VERSION 5.7 ;
  NOWIREEXTENSIONATPIN ON ;
  DIVIDERCHAR "/" ;
  BUSBITCHARS "[]" ;
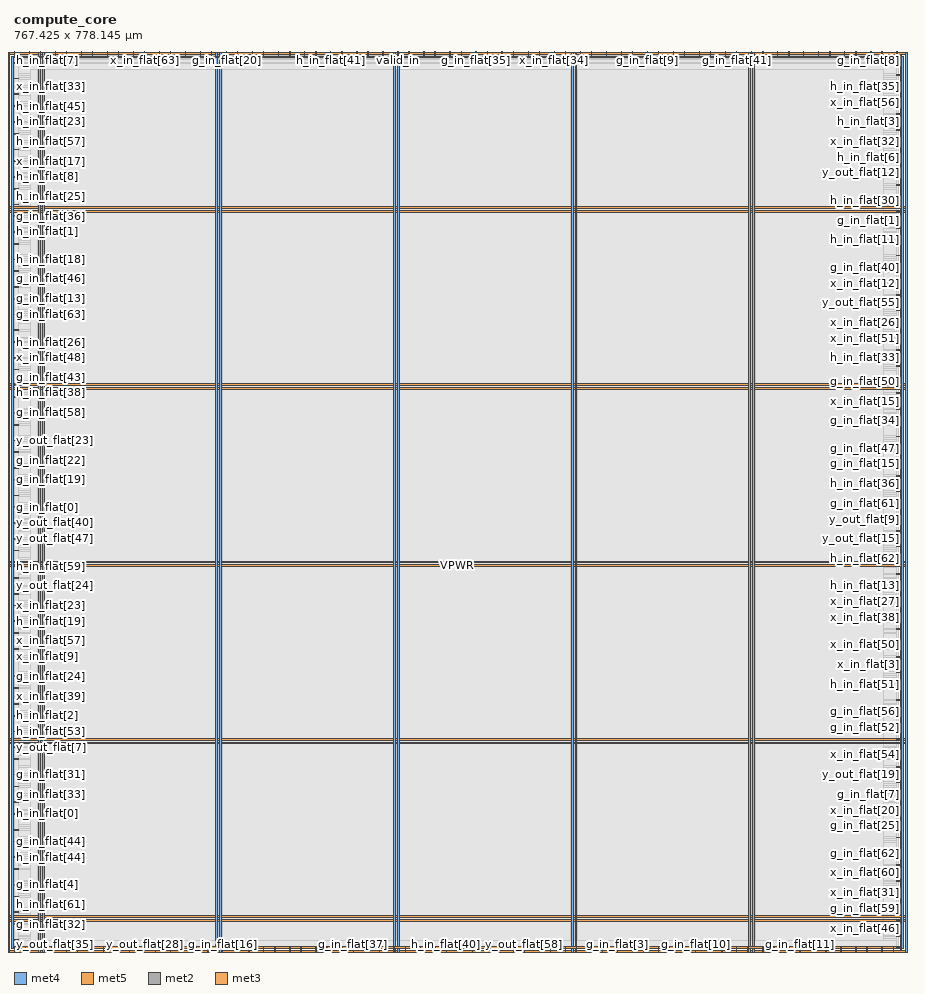
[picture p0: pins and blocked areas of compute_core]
MACRO compute_core
  CLASS BLOCK ;
  FOREIGN compute_core ;
  ORIGIN 0.000 0.000 ;
  SIZE 767.425 BY 778.145 ;
  PIN VGND
    DIRECTION INOUT ;
    USE GROUND ;
    PORT
      LAYER met4 ;
        RECT -5.380 -0.020 -3.780 777.940 ;
    END
    PORT
      LAYER met5 ;
        RECT -5.380 -0.020 772.660 1.580 ;
    END
    PORT
      LAYER met5 ;
        RECT -5.380 776.340 772.660 777.940 ;
    END
    PORT
      LAYER met4 ;
        RECT 771.060 -0.020 772.660 777.940 ;
    END
    PORT
      LAYER met4 ;
        RECT 24.340 -0.020 25.940 777.940 ;
    END
    PORT
      LAYER met4 ;
        RECT 177.940 -0.020 179.540 777.940 ;
    END
    PORT
      LAYER met4 ;
        RECT 331.540 -0.020 333.140 777.940 ;
    END
    PORT
      LAYER met4 ;
        RECT 485.140 -0.020 486.740 777.940 ;
    END
    PORT
      LAYER met4 ;
        RECT 638.740 -0.020 640.340 777.940 ;
    END
    PORT
      LAYER met5 ;
        RECT -5.380 30.030 772.660 31.630 ;
    END
    PORT
      LAYER met5 ;
        RECT -5.380 183.210 772.660 184.810 ;
    END
    PORT
      LAYER met5 ;
        RECT -5.380 336.390 772.660 337.990 ;
    END
    PORT
      LAYER met5 ;
        RECT -5.380 489.570 772.660 491.170 ;
    END
    PORT
      LAYER met5 ;
        RECT -5.380 642.750 772.660 644.350 ;
    END
  END VGND
  PIN VPWR
    DIRECTION INOUT ;
    USE POWER ;
    PORT
      LAYER met4 ;
        RECT -2.080 3.280 -0.480 774.640 ;
    END
    PORT
      LAYER met5 ;
        RECT -2.080 3.280 769.360 4.880 ;
    END
    PORT
      LAYER met5 ;
        RECT -2.080 773.040 769.360 774.640 ;
    END
    PORT
      LAYER met4 ;
        RECT 767.760 3.280 769.360 774.640 ;
    END
    PORT
      LAYER met4 ;
        RECT 21.040 -0.020 22.640 777.940 ;
    END
    PORT
      LAYER met4 ;
        RECT 174.640 -0.020 176.240 777.940 ;
    END
    PORT
      LAYER met4 ;
        RECT 328.240 -0.020 329.840 777.940 ;
    END
    PORT
      LAYER met4 ;
        RECT 481.840 -0.020 483.440 777.940 ;
    END
    PORT
      LAYER met4 ;
        RECT 635.440 -0.020 637.040 777.940 ;
    END
    PORT
      LAYER met5 ;
        RECT -5.380 26.730 772.660 28.330 ;
    END
    PORT
      LAYER met5 ;
        RECT -5.380 179.910 772.660 181.510 ;
    END
    PORT
      LAYER met5 ;
        RECT -5.380 333.090 772.660 334.690 ;
    END
    PORT
      LAYER met5 ;
        RECT -5.380 486.270 772.660 487.870 ;
    END
    PORT
      LAYER met5 ;
        RECT -5.380 639.450 772.660 641.050 ;
    END
  END VPWR
  PIN clk
    DIRECTION INPUT ;
    USE SIGNAL ;
    ANTENNAGATEAREA 1.286700 ;
    ANTENNADIFFAREA 0.434700 ;
    PORT
      LAYER met2 ;
        RECT 80.590 774.145 80.870 778.145 ;
    END
  END clk
  PIN compute_en
    DIRECTION INPUT ;
    USE SIGNAL ;
    ANTENNAGATEAREA 0.495000 ;
    PORT
      LAYER met3 ;
        RECT 0.000 71.440 4.000 72.040 ;
    END
  END compute_en
  PIN g_in_flat[0]
    DIRECTION INPUT ;
    USE SIGNAL ;
    ANTENNAGATEAREA 0.426000 ;
    PORT
      LAYER met3 ;
        RECT 0.000 384.240 4.000 384.840 ;
    END
  END g_in_flat[0]
  PIN g_in_flat[10]
    DIRECTION INPUT ;
    USE SIGNAL ;
    ANTENNAGATEAREA 0.213000 ;
    PORT
      LAYER met2 ;
        RECT 589.350 0.000 589.630 4.000 ;
    END
  END g_in_flat[10]
  PIN g_in_flat[11]
    DIRECTION INPUT ;
    USE SIGNAL ;
    ANTENNAGATEAREA 0.213000 ;
    PORT
      LAYER met2 ;
        RECT 679.510 0.000 679.790 4.000 ;
    END
  END g_in_flat[11]
  PIN g_in_flat[12]
    DIRECTION INPUT ;
    USE SIGNAL ;
    ANTENNAGATEAREA 0.426000 ;
    PORT
      LAYER met2 ;
        RECT 251.250 774.145 251.530 778.145 ;
    END
  END g_in_flat[12]
  PIN g_in_flat[13]
    DIRECTION INPUT ;
    USE SIGNAL ;
    ANTENNAGATEAREA 0.495000 ;
    PORT
      LAYER met3 ;
        RECT 0.000 564.440 4.000 565.040 ;
    END
  END g_in_flat[13]
  PIN g_in_flat[14]
    DIRECTION INPUT ;
    USE SIGNAL ;
    ANTENNAGATEAREA 0.213000 ;
    PORT
      LAYER met3 ;
        RECT 763.425 3.440 767.425 4.040 ;
    END
  END g_in_flat[14]
  PIN g_in_flat[15]
    DIRECTION INPUT ;
    USE SIGNAL ;
    ANTENNAGATEAREA 0.196500 ;
    PORT
      LAYER met3 ;
        RECT 763.425 421.640 767.425 422.240 ;
    END
  END g_in_flat[15]
  PIN g_in_flat[16]
    DIRECTION INPUT ;
    USE SIGNAL ;
    ANTENNAGATEAREA 0.213000 ;
    PORT
      LAYER met2 ;
        RECT 180.410 0.000 180.690 4.000 ;
    END
  END g_in_flat[16]
  PIN g_in_flat[17]
    DIRECTION INPUT ;
    USE SIGNAL ;
    ANTENNAGATEAREA 0.213000 ;
    PORT
      LAYER met3 ;
        RECT 0.000 10.240 4.000 10.840 ;
    END
  END g_in_flat[17]
  PIN g_in_flat[18]
    DIRECTION INPUT ;
    USE SIGNAL ;
    ANTENNAGATEAREA 0.196500 ;
    PORT
      LAYER met2 ;
        RECT 193.290 0.000 193.570 4.000 ;
    END
  END g_in_flat[18]
  PIN g_in_flat[19]
    DIRECTION INPUT ;
    USE SIGNAL ;
    ANTENNAGATEAREA 0.213000 ;
    PORT
      LAYER met3 ;
        RECT 0.000 408.040 4.000 408.640 ;
    END
  END g_in_flat[19]
  PIN g_in_flat[1]
    DIRECTION INPUT ;
    USE SIGNAL ;
    ANTENNAGATEAREA 0.213000 ;
    PORT
      LAYER met3 ;
        RECT 763.425 625.640 767.425 626.240 ;
    END
  END g_in_flat[1]
  PIN g_in_flat[20]
    DIRECTION INPUT ;
    USE SIGNAL ;
    ANTENNAGATEAREA 0.247500 ;
    PORT
      LAYER met2 ;
        RECT 183.630 774.145 183.910 778.145 ;
    END
  END g_in_flat[20]
  PIN g_in_flat[21]
    DIRECTION INPUT ;
    USE SIGNAL ;
    ANTENNAGATEAREA 0.247500 ;
    PORT
      LAYER met2 ;
        RECT 193.290 774.145 193.570 778.145 ;
    END
  END g_in_flat[21]
  PIN g_in_flat[22]
    DIRECTION INPUT ;
    USE SIGNAL ;
    ANTENNAGATEAREA 0.213000 ;
    PORT
      LAYER met3 ;
        RECT 0.000 418.240 4.000 418.840 ;
    END
  END g_in_flat[22]
  PIN g_in_flat[23]
    DIRECTION INPUT ;
    USE SIGNAL ;
    ANTENNAGATEAREA 0.213000 ;
    PORT
      LAYER met2 ;
        RECT 45.170 0.000 45.450 4.000 ;
    END
  END g_in_flat[23]
  PIN g_in_flat[24]
    DIRECTION INPUT ;
    USE SIGNAL ;
    ANTENNAGATEAREA 0.213000 ;
    PORT
      LAYER met3 ;
        RECT 0.000 238.040 4.000 238.640 ;
    END
  END g_in_flat[24]
  PIN g_in_flat[25]
    DIRECTION INPUT ;
    USE SIGNAL ;
    ANTENNAGATEAREA 0.426000 ;
    PORT
      LAYER met3 ;
        RECT 763.425 108.840 767.425 109.440 ;
    END
  END g_in_flat[25]
  PIN g_in_flat[26]
    DIRECTION INPUT ;
    USE SIGNAL ;
    ANTENNAGATEAREA 0.213000 ;
    PORT
      LAYER met2 ;
        RECT 409.030 774.145 409.310 778.145 ;
    END
  END g_in_flat[26]
  PIN g_in_flat[27]
    DIRECTION INPUT ;
    USE SIGNAL ;
    ANTENNAGATEAREA 0.742500 ;
    PORT
      LAYER met2 ;
        RECT 624.770 0.000 625.050 4.000 ;
    END
  END g_in_flat[27]
  PIN g_in_flat[28]
    DIRECTION INPUT ;
    USE SIGNAL ;
    ANTENNAGATEAREA 0.213000 ;
    PORT
      LAYER met2 ;
        RECT 67.710 774.145 67.990 778.145 ;
    END
  END g_in_flat[28]
  PIN g_in_flat[29]
    DIRECTION INPUT ;
    USE SIGNAL ;
    ANTENNAGATEAREA 0.159000 ;
    PORT
      LAYER met2 ;
        RECT 376.830 774.145 377.110 778.145 ;
    END
  END g_in_flat[29]
  PIN g_in_flat[2]
    DIRECTION INPUT ;
    USE SIGNAL ;
    ANTENNAGATEAREA 0.426000 ;
    PORT
      LAYER met2 ;
        RECT 225.490 0.000 225.770 4.000 ;
    END
  END g_in_flat[2]
  PIN g_in_flat[30]
    DIRECTION INPUT ;
    USE SIGNAL ;
    ANTENNAGATEAREA 0.159000 ;
    PORT
      LAYER met2 ;
        RECT 58.050 774.145 58.330 778.145 ;
    END
  END g_in_flat[30]
  PIN g_in_flat[31]
    DIRECTION INPUT ;
    USE SIGNAL ;
    ANTENNAGATEAREA 0.159000 ;
    PORT
      LAYER met3 ;
        RECT 0.000 153.040 4.000 153.640 ;
    END
  END g_in_flat[31]
  PIN g_in_flat[32]
    DIRECTION INPUT ;
    USE SIGNAL ;
    ANTENNAGATEAREA 0.213000 ;
    PORT
      LAYER met3 ;
        RECT 0.000 23.840 4.000 24.440 ;
    END
  END g_in_flat[32]
  PIN g_in_flat[33]
    DIRECTION INPUT ;
    USE SIGNAL ;
    ANTENNAGATEAREA 0.247500 ;
    PORT
      LAYER met3 ;
        RECT 0.000 142.840 4.000 143.440 ;
    END
  END g_in_flat[33]
  PIN g_in_flat[34]
    DIRECTION INPUT ;
    USE SIGNAL ;
    ANTENNAGATEAREA 0.426000 ;
    PORT
      LAYER met3 ;
        RECT 763.425 459.040 767.425 459.640 ;
    END
  END g_in_flat[34]
  PIN g_in_flat[35]
    DIRECTION INPUT ;
    USE SIGNAL ;
    ANTENNAGATEAREA 0.247500 ;
    PORT
      LAYER met2 ;
        RECT 399.370 774.145 399.650 778.145 ;
    END
  END g_in_flat[35]
  PIN g_in_flat[36]
    DIRECTION INPUT ;
    USE SIGNAL ;
    ANTENNAGATEAREA 0.159000 ;
    PORT
      LAYER met3 ;
        RECT 0.000 635.840 4.000 636.440 ;
    END
  END g_in_flat[36]
  PIN g_in_flat[37]
    DIRECTION INPUT ;
    USE SIGNAL ;
    ANTENNAGATEAREA 0.213000 ;
    PORT
      LAYER met2 ;
        RECT 293.110 0.000 293.390 4.000 ;
    END
  END g_in_flat[37]
  PIN g_in_flat[38]
    DIRECTION INPUT ;
    USE SIGNAL ;
    ANTENNAGATEAREA 0.213000 ;
    PORT
      LAYER met2 ;
        RECT 167.530 0.000 167.810 4.000 ;
    END
  END g_in_flat[38]
  PIN g_in_flat[39]
    DIRECTION INPUT ;
    USE SIGNAL ;
    ANTENNAGATEAREA 0.213000 ;
    PORT
      LAYER met2 ;
        RECT 125.670 774.145 125.950 778.145 ;
    END
  END g_in_flat[39]
  PIN g_in_flat[3]
    DIRECTION INPUT ;
    USE SIGNAL ;
    ANTENNAGATEAREA 0.247500 ;
    PORT
      LAYER met2 ;
        RECT 521.730 0.000 522.010 4.000 ;
    END
  END g_in_flat[3]
  PIN g_in_flat[40]
    DIRECTION INPUT ;
    USE SIGNAL ;
    ANTENNAGATEAREA 0.495000 ;
    PORT
      LAYER met3 ;
        RECT 763.425 591.640 767.425 592.240 ;
    END
  END g_in_flat[40]
  PIN g_in_flat[41]
    DIRECTION INPUT ;
    USE SIGNAL ;
    ANTENNAGATEAREA 0.742500 ;
    PORT
      LAYER met2 ;
        RECT 624.770 774.145 625.050 778.145 ;
    END
  END g_in_flat[41]
  PIN g_in_flat[42]
    DIRECTION INPUT ;
    USE SIGNAL ;
    ANTENNAGATEAREA 0.247500 ;
    PORT
      LAYER met2 ;
        RECT 238.370 774.145 238.650 778.145 ;
    END
  END g_in_flat[42]
  PIN g_in_flat[43]
    DIRECTION INPUT ;
    USE SIGNAL ;
    ANTENNAGATEAREA 0.159000 ;
    PORT
      LAYER met3 ;
        RECT 0.000 503.240 4.000 503.840 ;
    END
  END g_in_flat[43]
  PIN g_in_flat[44]
    DIRECTION INPUT ;
    USE SIGNAL ;
    ANTENNAGATEAREA 0.213000 ;
    PORT
      LAYER met3 ;
        RECT 0.000 95.240 4.000 95.840 ;
    END
  END g_in_flat[44]
  PIN g_in_flat[45]
    DIRECTION INPUT ;
    USE SIGNAL ;
    ANTENNAGATEAREA 0.159000 ;
    PORT
      LAYER met3 ;
        RECT 0.000 309.440 4.000 310.040 ;
    END
  END g_in_flat[45]
  PIN g_in_flat[46]
    DIRECTION INPUT ;
    USE SIGNAL ;
    ANTENNAGATEAREA 0.213000 ;
    PORT
      LAYER met3 ;
        RECT 0.000 588.240 4.000 588.840 ;
    END
  END g_in_flat[46]
  PIN g_in_flat[47]
    DIRECTION INPUT ;
    USE SIGNAL ;
    ANTENNAGATEAREA 0.247500 ;
    PORT
      LAYER met3 ;
        RECT 763.425 435.240 767.425 435.840 ;
    END
  END g_in_flat[47]
  PIN g_in_flat[48]
    DIRECTION INPUT ;
    USE SIGNAL ;
    ANTENNAGATEAREA 0.742500 ;
    PORT
      LAYER met3 ;
        RECT 0.000 768.440 4.000 769.040 ;
    END
  END g_in_flat[48]
  PIN g_in_flat[49]
    DIRECTION INPUT ;
    USE SIGNAL ;
    ANTENNAGATEAREA 0.247500 ;
    PORT
      LAYER met2 ;
        RECT 305.990 0.000 306.270 4.000 ;
    END
  END g_in_flat[49]
  PIN g_in_flat[4]
    DIRECTION INPUT ;
    USE SIGNAL ;
    ANTENNAGATEAREA 0.495000 ;
    PORT
      LAYER met3 ;
        RECT 0.000 57.840 4.000 58.440 ;
    END
  END g_in_flat[4]
  PIN g_in_flat[50]
    DIRECTION INPUT ;
    USE SIGNAL ;
    ANTENNAGATEAREA 0.159000 ;
    PORT
      LAYER met3 ;
        RECT 763.425 493.040 767.425 493.640 ;
    END
  END g_in_flat[50]
  PIN g_in_flat[51]
    DIRECTION INPUT ;
    USE SIGNAL ;
    ANTENNAGATEAREA 0.247500 ;
    PORT
      LAYER met2 ;
        RECT 122.450 0.000 122.730 4.000 ;
    END
  END g_in_flat[51]
  PIN g_in_flat[52]
    DIRECTION INPUT ;
    USE SIGNAL ;
    ANTENNAGATEAREA 0.196500 ;
    PORT
      LAYER met3 ;
        RECT 763.425 193.840 767.425 194.440 ;
    END
  END g_in_flat[52]
  PIN g_in_flat[53]
    DIRECTION INPUT ;
    USE SIGNAL ;
    ANTENNAGATEAREA 0.426000 ;
    PORT
      LAYER met2 ;
        RECT 444.450 774.145 444.730 778.145 ;
    END
  END g_in_flat[53]
  PIN g_in_flat[54]
    DIRECTION INPUT ;
    USE SIGNAL ;
    ANTENNAGATEAREA 0.247500 ;
    PORT
      LAYER met2 ;
        RECT 315.650 0.000 315.930 4.000 ;
    END
  END g_in_flat[54]
  PIN g_in_flat[55]
    DIRECTION INPUT ;
    USE SIGNAL ;
    ANTENNAGATEAREA 0.742500 ;
    PORT
      LAYER met2 ;
        RECT 22.630 774.145 22.910 778.145 ;
    END
  END g_in_flat[55]
  PIN g_in_flat[56]
    DIRECTION INPUT ;
    USE SIGNAL ;
    ANTENNAGATEAREA 0.213000 ;
    PORT
      LAYER met3 ;
        RECT 763.425 207.440 767.425 208.040 ;
    END
  END g_in_flat[56]
  PIN g_in_flat[57]
    DIRECTION INPUT ;
    USE SIGNAL ;
    ANTENNAGATEAREA 0.213000 ;
    PORT
      LAYER met2 ;
        RECT 737.470 0.000 737.750 4.000 ;
    END
  END g_in_flat[57]
  PIN g_in_flat[58]
    DIRECTION INPUT ;
    USE SIGNAL ;
    ANTENNAGATEAREA 0.495000 ;
    PORT
      LAYER met3 ;
        RECT 0.000 465.840 4.000 466.440 ;
    END
  END g_in_flat[58]
  PIN g_in_flat[59]
    DIRECTION INPUT ;
    USE SIGNAL ;
    ANTENNAGATEAREA 0.159000 ;
    PORT
      LAYER met3 ;
        RECT 763.425 37.440 767.425 38.040 ;
    END
  END g_in_flat[59]
  PIN g_in_flat[5]
    DIRECTION INPUT ;
    USE SIGNAL ;
    ANTENNAGATEAREA 0.159000 ;
    PORT
      LAYER met2 ;
        RECT 499.190 774.145 499.470 778.145 ;
    END
  END g_in_flat[5]
  PIN g_in_flat[60]
    DIRECTION INPUT ;
    USE SIGNAL ;
    ANTENNAGATEAREA 0.247500 ;
    PORT
      LAYER met2 ;
        RECT 647.310 774.145 647.590 778.145 ;
    END
  END g_in_flat[60]
  PIN g_in_flat[61]
    DIRECTION INPUT ;
    USE SIGNAL ;
    ANTENNAGATEAREA 0.213000 ;
    PORT
      LAYER met3 ;
        RECT 763.425 387.640 767.425 388.240 ;
    END
  END g_in_flat[61]
  PIN g_in_flat[62]
    DIRECTION INPUT ;
    USE SIGNAL ;
    ANTENNAGATEAREA 0.159000 ;
    PORT
      LAYER met3 ;
        RECT 763.425 85.040 767.425 85.640 ;
    END
  END g_in_flat[62]
  PIN g_in_flat[63]
    DIRECTION INPUT ;
    USE SIGNAL ;
    ANTENNAGATEAREA 0.196500 ;
    PORT
      LAYER met3 ;
        RECT 0.000 550.840 4.000 551.440 ;
    END
  END g_in_flat[63]
  PIN g_in_flat[6]
    DIRECTION INPUT ;
    USE SIGNAL ;
    ANTENNAGATEAREA 0.495000 ;
    PORT
      LAYER met3 ;
        RECT 0.000 105.440 4.000 106.040 ;
    END
  END g_in_flat[6]
  PIN g_in_flat[7]
    DIRECTION INPUT ;
    USE SIGNAL ;
    ANTENNAGATEAREA 0.213000 ;
    PORT
      LAYER met3 ;
        RECT 763.425 136.040 767.425 136.640 ;
    END
  END g_in_flat[7]
  PIN g_in_flat[8]
    DIRECTION INPUT ;
    USE SIGNAL ;
    ANTENNAGATEAREA 0.213000 ;
    PORT
      LAYER met2 ;
        RECT 750.350 774.145 750.630 778.145 ;
    END
  END g_in_flat[8]
  PIN g_in_flat[9]
    DIRECTION INPUT ;
    USE SIGNAL ;
    ANTENNAGATEAREA 0.247500 ;
    PORT
      LAYER met2 ;
        RECT 547.490 774.145 547.770 778.145 ;
    END
  END g_in_flat[9]
  PIN h_in_flat[0]
    DIRECTION INPUT ;
    USE SIGNAL ;
    ANTENNAGATEAREA 0.852000 ;
    PORT
      LAYER met3 ;
        RECT 0.000 119.040 4.000 119.640 ;
    END
  END h_in_flat[0]
  PIN h_in_flat[10]
    DIRECTION INPUT ;
    USE SIGNAL ;
    ANTENNAGATEAREA 0.213000 ;
    PORT
      LAYER met2 ;
        RECT 570.030 774.145 570.310 778.145 ;
    END
  END h_in_flat[10]
  PIN h_in_flat[11]
    DIRECTION INPUT ;
    USE SIGNAL ;
    ANTENNAGATEAREA 0.213000 ;
    PORT
      LAYER met3 ;
        RECT 763.425 615.440 767.425 616.040 ;
    END
  END h_in_flat[11]
  PIN h_in_flat[12]
    DIRECTION INPUT ;
    USE SIGNAL ;
    ANTENNAGATEAREA 0.742500 ;
    PORT
      LAYER met2 ;
        RECT 77.370 0.000 77.650 4.000 ;
    END
  END h_in_flat[12]
  PIN h_in_flat[13]
    DIRECTION INPUT ;
    USE SIGNAL ;
    ANTENNAGATEAREA 0.247500 ;
    PORT
      LAYER met3 ;
        RECT 763.425 316.240 767.425 316.840 ;
    END
  END h_in_flat[13]
  PIN h_in_flat[14]
    DIRECTION INPUT ;
    USE SIGNAL ;
    ANTENNAGATEAREA 0.247500 ;
    PORT
      LAYER met2 ;
        RECT 579.690 0.000 579.970 4.000 ;
    END
  END h_in_flat[14]
  PIN h_in_flat[15]
    DIRECTION INPUT ;
    USE SIGNAL ;
    ANTENNAGATEAREA 0.213000 ;
    PORT
      LAYER met2 ;
        RECT 727.810 774.145 728.090 778.145 ;
    END
  END h_in_flat[15]
  PIN h_in_flat[16]
    DIRECTION INPUT ;
    USE SIGNAL ;
    ANTENNAGATEAREA 0.213000 ;
    PORT
      LAYER met2 ;
        RECT 170.750 774.145 171.030 778.145 ;
    END
  END h_in_flat[16]
  PIN h_in_flat[17]
    DIRECTION INPUT ;
    USE SIGNAL ;
    ANTENNAGATEAREA 0.742500 ;
    PORT
      LAYER met2 ;
        RECT 418.690 0.000 418.970 4.000 ;
    END
  END h_in_flat[17]
  PIN h_in_flat[18]
    DIRECTION INPUT ;
    USE SIGNAL ;
    ANTENNAGATEAREA 0.213000 ;
    PORT
      LAYER met3 ;
        RECT 0.000 598.440 4.000 599.040 ;
    END
  END h_in_flat[18]
  PIN h_in_flat[19]
    DIRECTION INPUT ;
    USE SIGNAL ;
    ANTENNAGATEAREA 0.247500 ;
    PORT
      LAYER met3 ;
        RECT 0.000 285.640 4.000 286.240 ;
    END
  END h_in_flat[19]
  PIN h_in_flat[1]
    DIRECTION INPUT ;
    USE SIGNAL ;
    ANTENNAGATEAREA 0.495000 ;
    PORT
      LAYER met3 ;
        RECT 0.000 622.240 4.000 622.840 ;
    END
  END h_in_flat[1]
  PIN h_in_flat[20]
    DIRECTION INPUT ;
    USE SIGNAL ;
    ANTENNAGATEAREA 0.742500 ;
    PORT
      LAYER met2 ;
        RECT 499.190 0.000 499.470 4.000 ;
    END
  END h_in_flat[20]
  PIN h_in_flat[21]
    DIRECTION INPUT ;
    USE SIGNAL ;
    ANTENNAGATEAREA 0.852000 ;
    PORT
      LAYER met2 ;
        RECT 647.310 0.000 647.590 4.000 ;
    END
  END h_in_flat[21]
  PIN h_in_flat[22]
    DIRECTION INPUT ;
    USE SIGNAL ;
    ANTENNAGATEAREA 0.742500 ;
    PORT
      LAYER met2 ;
        RECT 692.390 0.000 692.670 4.000 ;
    END
  END h_in_flat[22]
  PIN h_in_flat[23]
    DIRECTION INPUT ;
    USE SIGNAL ;
    ANTENNAGATEAREA 0.213000 ;
    PORT
      LAYER met3 ;
        RECT 0.000 717.440 4.000 718.040 ;
    END
  END h_in_flat[23]
  PIN h_in_flat[24]
    DIRECTION INPUT ;
    USE SIGNAL ;
    ANTENNAGATEAREA 0.990000 ;
    PORT
      LAYER met2 ;
        RECT 669.850 0.000 670.130 4.000 ;
    END
  END h_in_flat[24]
  PIN h_in_flat[25]
    DIRECTION INPUT ;
    USE SIGNAL ;
    ANTENNAGATEAREA 0.126000 ;
    PORT
      LAYER met3 ;
        RECT 0.000 646.040 4.000 646.640 ;
    END
  END h_in_flat[25]
  PIN h_in_flat[26]
    DIRECTION INPUT ;
    USE SIGNAL ;
    ANTENNAGATEAREA 0.159000 ;
    PORT
      LAYER met3 ;
        RECT 0.000 527.040 4.000 527.640 ;
    END
  END h_in_flat[26]
  PIN h_in_flat[27]
    DIRECTION INPUT ;
    USE SIGNAL ;
    ANTENNAGATEAREA 0.159000 ;
    PORT
      LAYER met2 ;
        RECT 283.450 774.145 283.730 778.145 ;
    END
  END h_in_flat[27]
  PIN h_in_flat[28]
    DIRECTION INPUT ;
    USE SIGNAL ;
    ANTENNAGATEAREA 0.426000 ;
    PORT
      LAYER met2 ;
        RECT 463.770 0.000 464.050 4.000 ;
    END
  END h_in_flat[28]
  PIN h_in_flat[29]
    DIRECTION INPUT ;
    USE SIGNAL ;
    ANTENNAGATEAREA 0.213000 ;
    PORT
      LAYER met2 ;
        RECT 421.910 774.145 422.190 778.145 ;
    END
  END h_in_flat[29]
  PIN h_in_flat[2]
    DIRECTION INPUT ;
    USE SIGNAL ;
    ANTENNAGATEAREA 0.742500 ;
    PORT
      LAYER met3 ;
        RECT 0.000 204.040 4.000 204.640 ;
    END
  END h_in_flat[2]
  PIN h_in_flat[30]
    DIRECTION INPUT ;
    USE SIGNAL ;
    ANTENNAGATEAREA 0.247500 ;
    PORT
      LAYER met3 ;
        RECT 763.425 649.440 767.425 650.040 ;
    END
  END h_in_flat[30]
  PIN h_in_flat[31]
    DIRECTION INPUT ;
    USE SIGNAL ;
    ANTENNAGATEAREA 0.159000 ;
    PORT
      LAYER met2 ;
        RECT 90.250 774.145 90.530 778.145 ;
    END
  END h_in_flat[31]
  PIN h_in_flat[32]
    DIRECTION INPUT ;
    USE SIGNAL ;
    ANTENNAGATEAREA 0.742500 ;
    PORT
      LAYER met2 ;
        RECT 611.890 0.000 612.170 4.000 ;
    END
  END h_in_flat[32]
  PIN h_in_flat[33]
    DIRECTION INPUT ;
    USE SIGNAL ;
    ANTENNAGATEAREA 0.426000 ;
    PORT
      LAYER met3 ;
        RECT 763.425 520.240 767.425 520.840 ;
    END
  END h_in_flat[33]
  PIN h_in_flat[34]
    DIRECTION INPUT ;
    USE SIGNAL ;
    ANTENNAGATEAREA 0.742500 ;
    PORT
      LAYER met2 ;
        RECT 702.050 0.000 702.330 4.000 ;
    END
  END h_in_flat[34]
  PIN h_in_flat[35]
    DIRECTION INPUT ;
    USE SIGNAL ;
    ANTENNAGATEAREA 0.213000 ;
    PORT
      LAYER met3 ;
        RECT 763.425 748.040 767.425 748.640 ;
    END
  END h_in_flat[35]
  PIN h_in_flat[36]
    DIRECTION INPUT ;
    USE SIGNAL ;
    ANTENNAGATEAREA 0.247500 ;
    PORT
      LAYER met3 ;
        RECT 763.425 411.440 767.425 412.040 ;
    END
  END h_in_flat[36]
  PIN h_in_flat[37]
    DIRECTION INPUT ;
    USE SIGNAL ;
    ANTENNAGATEAREA 0.213000 ;
    PORT
      LAYER met2 ;
        RECT 386.490 774.145 386.770 778.145 ;
    END
  END h_in_flat[37]
  PIN h_in_flat[38]
    DIRECTION INPUT ;
    USE SIGNAL ;
    ANTENNAGATEAREA 0.247500 ;
    PORT
      LAYER met3 ;
        RECT 0.000 489.640 4.000 490.240 ;
    END
  END h_in_flat[38]
  PIN h_in_flat[39]
    DIRECTION INPUT ;
    USE SIGNAL ;
    ANTENNAGATEAREA 0.213000 ;
    PORT
      LAYER met2 ;
        RECT 592.570 774.145 592.850 778.145 ;
    END
  END h_in_flat[39]
  PIN h_in_flat[3]
    DIRECTION INPUT ;
    USE SIGNAL ;
    ANTENNAGATEAREA 0.213000 ;
    PORT
      LAYER met3 ;
        RECT 763.425 724.240 767.425 724.840 ;
    END
  END h_in_flat[3]
  PIN h_in_flat[40]
    DIRECTION INPUT ;
    USE SIGNAL ;
    ANTENNAGATEAREA 0.426000 ;
    PORT
      LAYER met2 ;
        RECT 373.610 0.000 373.890 4.000 ;
    END
  END h_in_flat[40]
  PIN h_in_flat[41]
    DIRECTION INPUT ;
    USE SIGNAL ;
    ANTENNAGATEAREA 0.213000 ;
    PORT
      LAYER met2 ;
        RECT 273.790 774.145 274.070 778.145 ;
    END
  END h_in_flat[41]
  PIN h_in_flat[42]
    DIRECTION INPUT ;
    USE SIGNAL ;
    ANTENNAGATEAREA 0.247500 ;
    PORT
      LAYER met3 ;
        RECT 0.000 537.240 4.000 537.840 ;
    END
  END h_in_flat[42]
  PIN h_in_flat[43]
    DIRECTION INPUT ;
    USE SIGNAL ;
    ANTENNAGATEAREA 0.159000 ;
    PORT
      LAYER met2 ;
        RECT 341.410 774.145 341.690 778.145 ;
    END
  END h_in_flat[43]
  PIN h_in_flat[44]
    DIRECTION INPUT ;
    USE SIGNAL ;
    ANTENNAGATEAREA 0.742500 ;
    PORT
      LAYER met3 ;
        RECT 0.000 81.640 4.000 82.240 ;
    END
  END h_in_flat[44]
  PIN h_in_flat[45]
    DIRECTION INPUT ;
    USE SIGNAL ;
    ANTENNAGATEAREA 0.247500 ;
    PORT
      LAYER met3 ;
        RECT 0.000 731.040 4.000 731.640 ;
    END
  END h_in_flat[45]
  PIN h_in_flat[46]
    DIRECTION INPUT ;
    USE SIGNAL ;
    ANTENNAGATEAREA 0.495000 ;
    PORT
      LAYER met2 ;
        RECT 135.330 0.000 135.610 4.000 ;
    END
  END h_in_flat[46]
  PIN h_in_flat[47]
    DIRECTION INPUT ;
    USE SIGNAL ;
    ANTENNAGATEAREA 0.213000 ;
    PORT
      LAYER met3 ;
        RECT 0.000 394.440 4.000 395.040 ;
    END
  END h_in_flat[47]
  PIN h_in_flat[48]
    DIRECTION INPUT ;
    USE SIGNAL ;
    ANTENNAGATEAREA 0.213000 ;
    PORT
      LAYER met2 ;
        RECT 305.990 774.145 306.270 778.145 ;
    END
  END h_in_flat[48]
  PIN h_in_flat[49]
    DIRECTION INPUT ;
    USE SIGNAL ;
    ANTENNAGATEAREA 0.426000 ;
    PORT
      LAYER met3 ;
        RECT 763.425 397.840 767.425 398.440 ;
    END
  END h_in_flat[49]
  PIN h_in_flat[4]
    DIRECTION INPUT ;
    USE SIGNAL ;
    ANTENNAGATEAREA 0.742500 ;
    PORT
      LAYER met2 ;
        RECT 90.250 0.000 90.530 4.000 ;
    END
  END h_in_flat[4]
  PIN h_in_flat[50]
    DIRECTION INPUT ;
    USE SIGNAL ;
    ANTENNAGATEAREA 0.742500 ;
    PORT
      LAYER met2 ;
        RECT 760.010 0.000 760.290 4.000 ;
    END
  END h_in_flat[50]
  PIN h_in_flat[51]
    DIRECTION INPUT ;
    USE SIGNAL ;
    ANTENNAGATEAREA 0.495000 ;
    PORT
      LAYER met3 ;
        RECT 763.425 231.240 767.425 231.840 ;
    END
  END h_in_flat[51]
  PIN h_in_flat[52]
    DIRECTION INPUT ;
    USE SIGNAL ;
    ANTENNAGATEAREA 0.159000 ;
    PORT
      LAYER met2 ;
        RECT 206.170 774.145 206.450 778.145 ;
    END
  END h_in_flat[52]
  PIN h_in_flat[53]
    DIRECTION INPUT ;
    USE SIGNAL ;
    ANTENNAGATEAREA 0.247500 ;
    PORT
      LAYER met3 ;
        RECT 0.000 190.440 4.000 191.040 ;
    END
  END h_in_flat[53]
  PIN h_in_flat[54]
    DIRECTION INPUT ;
    USE SIGNAL ;
    ANTENNAGATEAREA 0.247500 ;
    PORT
      LAYER met2 ;
        RECT 682.730 774.145 683.010 778.145 ;
    END
  END h_in_flat[54]
  PIN h_in_flat[55]
    DIRECTION INPUT ;
    USE SIGNAL ;
    ANTENNAGATEAREA 0.247500 ;
    PORT
      LAYER met2 ;
        RECT 740.690 774.145 740.970 778.145 ;
    END
  END h_in_flat[55]
  PIN h_in_flat[56]
    DIRECTION INPUT ;
    USE SIGNAL ;
    ANTENNAGATEAREA 0.426000 ;
    PORT
      LAYER met2 ;
        RECT 260.910 0.000 261.190 4.000 ;
    END
  END h_in_flat[56]
  PIN h_in_flat[57]
    DIRECTION INPUT ;
    USE SIGNAL ;
    ANTENNAGATEAREA 0.213000 ;
    PORT
      LAYER met3 ;
        RECT 0.000 693.640 4.000 694.240 ;
    END
  END h_in_flat[57]
  PIN h_in_flat[58]
    DIRECTION INPUT ;
    USE SIGNAL ;
    ANTENNAGATEAREA 0.213000 ;
    PORT
      LAYER met3 ;
        RECT 0.000 431.840 4.000 432.440 ;
    END
  END h_in_flat[58]
  PIN h_in_flat[59]
    DIRECTION INPUT ;
    USE SIGNAL ;
    ANTENNAGATEAREA 0.213000 ;
    PORT
      LAYER met3 ;
        RECT 0.000 333.240 4.000 333.840 ;
    END
  END h_in_flat[59]
  PIN h_in_flat[5]
    DIRECTION INPUT ;
    USE SIGNAL ;
    ANTENNAGATEAREA 0.213000 ;
    PORT
      LAYER met2 ;
        RECT 354.290 774.145 354.570 778.145 ;
    END
  END h_in_flat[5]
  PIN h_in_flat[60]
    DIRECTION INPUT ;
    USE SIGNAL ;
    ANTENNAGATEAREA 0.247500 ;
    PORT
      LAYER met2 ;
        RECT 270.570 0.000 270.850 4.000 ;
    END
  END h_in_flat[60]
  PIN h_in_flat[61]
    DIRECTION INPUT ;
    USE SIGNAL ;
    ANTENNAGATEAREA 0.426000 ;
    PORT
      LAYER met3 ;
        RECT 0.000 47.640 4.000 48.240 ;
    END
  END h_in_flat[61]
  PIN h_in_flat[62]
    DIRECTION INPUT ;
    USE SIGNAL ;
    ANTENNAGATEAREA 0.426000 ;
    PORT
      LAYER met3 ;
        RECT 763.425 340.040 767.425 340.640 ;
    END
  END h_in_flat[62]
  PIN h_in_flat[63]
    DIRECTION INPUT ;
    USE SIGNAL ;
    ANTENNAGATEAREA 0.196500 ;
    PORT
      LAYER met2 ;
        RECT 318.870 774.145 319.150 778.145 ;
    END
  END h_in_flat[63]
  PIN h_in_flat[6]
    DIRECTION INPUT ;
    USE SIGNAL ;
    ANTENNAGATEAREA 0.159000 ;
    PORT
      LAYER met3 ;
        RECT 763.425 686.840 767.425 687.440 ;
    END
  END h_in_flat[6]
  PIN h_in_flat[7]
    DIRECTION INPUT ;
    USE SIGNAL ;
    ANTENNAGATEAREA 0.247500 ;
    PORT
      LAYER met2 ;
        RECT 12.970 774.145 13.250 778.145 ;
    END
  END h_in_flat[7]
  PIN h_in_flat[8]
    DIRECTION INPUT ;
    USE SIGNAL ;
    ANTENNAGATEAREA 0.426000 ;
    PORT
      LAYER met3 ;
        RECT 0.000 669.840 4.000 670.440 ;
    END
  END h_in_flat[8]
  PIN h_in_flat[9]
    DIRECTION INPUT ;
    USE SIGNAL ;
    ANTENNAGATEAREA 0.742500 ;
    PORT
      LAYER met2 ;
        RECT 238.370 0.000 238.650 4.000 ;
    END
  END h_in_flat[9]
  PIN load_en
    DIRECTION INPUT ;
    USE SIGNAL ;
    ANTENNAGATEAREA 0.495000 ;
    PORT
      LAYER met3 ;
        RECT 763.425 445.440 767.425 446.040 ;
    END
  END load_en
  PIN ready_in
    DIRECTION OUTPUT TRISTATE ;
    USE SIGNAL ;
    ANTENNADIFFAREA 0.795200 ;
    PORT
      LAYER met3 ;
        RECT 0.000 129.240 4.000 129.840 ;
    END
  END ready_in
  PIN ready_out
    DIRECTION INPUT ;
    USE SIGNAL ;
    ANTENNAGATEAREA 0.213000 ;
    PORT
      LAYER met2 ;
        RECT 45.170 774.145 45.450 778.145 ;
    END
  END ready_out
  PIN rst_n
    DIRECTION INPUT ;
    USE SIGNAL ;
    ANTENNAGATEAREA 0.126000 ;
    PORT
      LAYER met2 ;
        RECT 409.030 0.000 409.310 4.000 ;
    END
  END rst_n
  PIN valid_in
    DIRECTION INPUT ;
    USE SIGNAL ;
    ANTENNAGATEAREA 0.247500 ;
    PORT
      LAYER met2 ;
        RECT 331.750 774.145 332.030 778.145 ;
    END
  END valid_in
  PIN valid_out
    DIRECTION OUTPUT TRISTATE ;
    USE SIGNAL ;
    ANTENNADIFFAREA 0.795200 ;
    PORT
      LAYER met2 ;
        RECT 695.610 774.145 695.890 778.145 ;
    END
  END valid_out
  PIN w_in
    DIRECTION INPUT ;
    USE SIGNAL ;
    ANTENNAGATEAREA 0.159000 ;
    PORT
      LAYER met2 ;
        RECT 602.230 774.145 602.510 778.145 ;
    END
  END w_in
  PIN x_in_flat[0]
    DIRECTION INPUT ;
    USE SIGNAL ;
    ANTENNAGATEAREA 0.247500 ;
    PORT
      LAYER met2 ;
        RECT 763.230 774.145 763.510 778.145 ;
    END
  END x_in_flat[0]
  PIN x_in_flat[10]
    DIRECTION INPUT ;
    USE SIGNAL ;
    ANTENNAGATEAREA 0.213000 ;
    PORT
      LAYER met2 ;
        RECT 557.150 0.000 557.430 4.000 ;
    END
  END x_in_flat[10]
  PIN x_in_flat[11]
    DIRECTION INPUT ;
    USE SIGNAL ;
    ANTENNAGATEAREA 0.495000 ;
    PORT
      LAYER met2 ;
        RECT 35.510 774.145 35.790 778.145 ;
    END
  END x_in_flat[11]
  PIN x_in_flat[12]
    DIRECTION INPUT ;
    USE SIGNAL ;
    ANTENNAGATEAREA 0.159000 ;
    PORT
      LAYER met3 ;
        RECT 763.425 578.040 767.425 578.640 ;
    END
  END x_in_flat[12]
  PIN x_in_flat[13]
    DIRECTION INPUT ;
    USE SIGNAL ;
    ANTENNAGATEAREA 0.213000 ;
    PORT
      LAYER met3 ;
        RECT 763.425 98.640 767.425 99.240 ;
    END
  END x_in_flat[13]
  PIN x_in_flat[14]
    DIRECTION INPUT ;
    USE SIGNAL ;
    ANTENNAGATEAREA 0.247500 ;
    PORT
      LAYER met2 ;
        RECT 431.570 0.000 431.850 4.000 ;
    END
  END x_in_flat[14]
  PIN x_in_flat[15]
    DIRECTION INPUT ;
    USE SIGNAL ;
    ANTENNAGATEAREA 0.196500 ;
    PORT
      LAYER met3 ;
        RECT 763.425 469.240 767.425 469.840 ;
    END
  END x_in_flat[15]
  PIN x_in_flat[16]
    DIRECTION INPUT ;
    USE SIGNAL ;
    ANTENNAGATEAREA 0.426000 ;
    PORT
      LAYER met2 ;
        RECT 634.430 0.000 634.710 4.000 ;
    END
  END x_in_flat[16]
  PIN x_in_flat[17]
    DIRECTION INPUT ;
    USE SIGNAL ;
    ANTENNAGATEAREA 0.495000 ;
    PORT
      LAYER met3 ;
        RECT 0.000 683.440 4.000 684.040 ;
    END
  END x_in_flat[17]
  PIN x_in_flat[18]
    DIRECTION INPUT ;
    USE SIGNAL ;
    ANTENNAGATEAREA 0.247500 ;
    PORT
      LAYER met2 ;
        RECT 534.610 0.000 534.890 4.000 ;
    END
  END x_in_flat[18]
  PIN x_in_flat[19]
    DIRECTION INPUT ;
    USE SIGNAL ;
    ANTENNAGATEAREA 0.742500 ;
    PORT
      LAYER met2 ;
        RECT 524.950 774.145 525.230 778.145 ;
    END
  END x_in_flat[19]
  PIN x_in_flat[1]
    DIRECTION INPUT ;
    USE SIGNAL ;
    ANTENNAGATEAREA 0.495000 ;
    PORT
      LAYER met2 ;
        RECT 228.710 774.145 228.990 778.145 ;
    END
  END x_in_flat[1]
  PIN x_in_flat[20]
    DIRECTION INPUT ;
    USE SIGNAL ;
    ANTENNAGATEAREA 0.426000 ;
    PORT
      LAYER met3 ;
        RECT 763.425 122.440 767.425 123.040 ;
    END
  END x_in_flat[20]
  PIN x_in_flat[21]
    DIRECTION INPUT ;
    USE SIGNAL ;
    ANTENNAGATEAREA 0.213000 ;
    PORT
      LAYER met2 ;
        RECT 328.530 0.000 328.810 4.000 ;
    END
  END x_in_flat[21]
  PIN x_in_flat[22]
    DIRECTION INPUT ;
    USE SIGNAL ;
    ANTENNAGATEAREA 0.742500 ;
    PORT
      LAYER met3 ;
        RECT 763.425 217.640 767.425 218.240 ;
    END
  END x_in_flat[22]
  PIN x_in_flat[23]
    DIRECTION INPUT ;
    USE SIGNAL ;
    ANTENNAGATEAREA 0.426000 ;
    PORT
      LAYER met3 ;
        RECT 0.000 299.240 4.000 299.840 ;
    END
  END x_in_flat[23]
  PIN x_in_flat[24]
    DIRECTION INPUT ;
    USE SIGNAL ;
    ANTENNAGATEAREA 0.213000 ;
    PORT
      LAYER met3 ;
        RECT 0.000 34.040 4.000 34.640 ;
    END
  END x_in_flat[24]
  PIN x_in_flat[25]
    DIRECTION INPUT ;
    USE SIGNAL ;
    ANTENNAGATEAREA 0.852000 ;
    PORT
      LAYER met2 ;
        RECT 476.650 774.145 476.930 778.145 ;
    END
  END x_in_flat[25]
  PIN x_in_flat[26]
    DIRECTION INPUT ;
    USE SIGNAL ;
    ANTENNAGATEAREA 0.426000 ;
    PORT
      LAYER met3 ;
        RECT 763.425 544.040 767.425 544.640 ;
    END
  END x_in_flat[26]
  PIN x_in_flat[27]
    DIRECTION INPUT ;
    USE SIGNAL ;
    ANTENNAGATEAREA 0.495000 ;
    PORT
      LAYER met3 ;
        RECT 763.425 302.640 767.425 303.240 ;
    END
  END x_in_flat[27]
  PIN x_in_flat[28]
    DIRECTION INPUT ;
    USE SIGNAL ;
    ANTENNAGATEAREA 0.247500 ;
    PORT
      LAYER met2 ;
        RECT 615.110 774.145 615.390 778.145 ;
    END
  END x_in_flat[28]
  PIN x_in_flat[29]
    DIRECTION INPUT ;
    USE SIGNAL ;
    ANTENNAGATEAREA 0.247500 ;
    PORT
      LAYER met2 ;
        RECT 660.190 774.145 660.470 778.145 ;
    END
  END x_in_flat[29]
  PIN x_in_flat[2]
    DIRECTION INPUT ;
    USE SIGNAL ;
    ANTENNAGATEAREA 0.213000 ;
    PORT
      LAYER met2 ;
        RECT 714.930 0.000 715.210 4.000 ;
    END
  END x_in_flat[2]
  PIN x_in_flat[30]
    DIRECTION INPUT ;
    USE SIGNAL ;
    ANTENNAGATEAREA 0.126000 ;
    PORT
      LAYER met2 ;
        RECT 215.830 774.145 216.110 778.145 ;
    END
  END x_in_flat[30]
  PIN x_in_flat[31]
    DIRECTION INPUT ;
    USE SIGNAL ;
    ANTENNAGATEAREA 0.247500 ;
    PORT
      LAYER met3 ;
        RECT 763.425 51.040 767.425 51.640 ;
    END
  END x_in_flat[31]
  PIN x_in_flat[32]
    DIRECTION INPUT ;
    USE SIGNAL ;
    ANTENNAGATEAREA 0.742500 ;
    PORT
      LAYER met3 ;
        RECT 763.425 700.440 767.425 701.040 ;
    END
  END x_in_flat[32]
  PIN x_in_flat[33]
    DIRECTION INPUT ;
    USE SIGNAL ;
    ANTENNAGATEAREA 0.247500 ;
    PORT
      LAYER met3 ;
        RECT 0.000 741.240 4.000 741.840 ;
    END
  END x_in_flat[33]
  PIN x_in_flat[34]
    DIRECTION INPUT ;
    USE SIGNAL ;
    ANTENNAGATEAREA 0.742500 ;
    PORT
      LAYER met2 ;
        RECT 466.990 774.145 467.270 778.145 ;
    END
  END x_in_flat[34]
  PIN x_in_flat[35]
    DIRECTION INPUT ;
    USE SIGNAL ;
    ANTENNAGATEAREA 0.213000 ;
    PORT
      LAYER met3 ;
        RECT 0.000 455.640 4.000 456.240 ;
    END
  END x_in_flat[35]
  PIN x_in_flat[36]
    DIRECTION INPUT ;
    USE SIGNAL ;
    ANTENNAGATEAREA 0.247500 ;
    PORT
      LAYER met2 ;
        RECT 338.190 0.000 338.470 4.000 ;
    END
  END x_in_flat[36]
  PIN x_in_flat[37]
    DIRECTION INPUT ;
    USE SIGNAL ;
    ANTENNAGATEAREA 0.495000 ;
    PORT
      LAYER met3 ;
        RECT 763.425 326.440 767.425 327.040 ;
    END
  END x_in_flat[37]
  PIN x_in_flat[38]
    DIRECTION INPUT ;
    USE SIGNAL ;
    ANTENNAGATEAREA 0.742500 ;
    PORT
      LAYER met3 ;
        RECT 763.425 289.040 767.425 289.640 ;
    END
  END x_in_flat[38]
  PIN x_in_flat[39]
    DIRECTION INPUT ;
    USE SIGNAL ;
    ANTENNAGATEAREA 0.213000 ;
    PORT
      LAYER met3 ;
        RECT 0.000 214.240 4.000 214.840 ;
    END
  END x_in_flat[39]
  PIN x_in_flat[3]
    DIRECTION INPUT ;
    USE SIGNAL ;
    ANTENNAGATEAREA 0.247500 ;
    PORT
      LAYER met3 ;
        RECT 763.425 241.440 767.425 242.040 ;
    END
  END x_in_flat[3]
  PIN x_in_flat[40]
    DIRECTION INPUT ;
    USE SIGNAL ;
    ANTENNAGATEAREA 0.742500 ;
    PORT
      LAYER met3 ;
        RECT 763.425 61.240 767.425 61.840 ;
    END
  END x_in_flat[40]
  PIN x_in_flat[41]
    DIRECTION INPUT ;
    USE SIGNAL ;
    ANTENNAGATEAREA 0.426000 ;
    PORT
      LAYER met2 ;
        RECT 602.230 0.000 602.510 4.000 ;
    END
  END x_in_flat[41]
  PIN x_in_flat[42]
    DIRECTION INPUT ;
    USE SIGNAL ;
    ANTENNAGATEAREA 0.495000 ;
    PORT
      LAYER met3 ;
        RECT 763.425 758.240 767.425 758.840 ;
    END
  END x_in_flat[42]
  PIN x_in_flat[43]
    DIRECTION INPUT ;
    USE SIGNAL ;
    ANTENNAGATEAREA 0.213000 ;
    PORT
      LAYER met3 ;
        RECT 0.000 166.640 4.000 167.240 ;
    END
  END x_in_flat[43]
  PIN x_in_flat[44]
    DIRECTION INPUT ;
    USE SIGNAL ;
    ANTENNAGATEAREA 0.426000 ;
    PORT
      LAYER met2 ;
        RECT 363.950 0.000 364.230 4.000 ;
    END
  END x_in_flat[44]
  PIN x_in_flat[45]
    DIRECTION INPUT ;
    USE SIGNAL ;
    ANTENNAGATEAREA 0.213000 ;
    PORT
      LAYER met2 ;
        RECT 148.210 774.145 148.490 778.145 ;
    END
  END x_in_flat[45]
  PIN x_in_flat[46]
    DIRECTION INPUT ;
    USE SIGNAL ;
    ANTENNAGATEAREA 0.742500 ;
    PORT
      LAYER met3 ;
        RECT 763.425 13.640 767.425 14.240 ;
    END
  END x_in_flat[46]
  PIN x_in_flat[47]
    DIRECTION INPUT ;
    USE SIGNAL ;
    ANTENNAGATEAREA 0.247500 ;
    PORT
      LAYER met2 ;
        RECT 431.570 774.145 431.850 778.145 ;
    END
  END x_in_flat[47]
  PIN x_in_flat[48]
    DIRECTION INPUT ;
    USE SIGNAL ;
    ANTENNAGATEAREA 0.742500 ;
    PORT
      LAYER met3 ;
        RECT 0.000 513.440 4.000 514.040 ;
    END
  END x_in_flat[48]
  PIN x_in_flat[49]
    DIRECTION INPUT ;
    USE SIGNAL ;
    ANTENNAGATEAREA 0.742500 ;
    PORT
      LAYER met2 ;
        RECT 67.710 0.000 67.990 4.000 ;
    END
  END x_in_flat[49]
  PIN x_in_flat[4]
    DIRECTION INPUT ;
    USE SIGNAL ;
    ANTENNAGATEAREA 0.247500 ;
    PORT
      LAYER met2 ;
        RECT 557.150 774.145 557.430 778.145 ;
    END
  END x_in_flat[4]
  PIN x_in_flat[50]
    DIRECTION INPUT ;
    USE SIGNAL ;
    ANTENNAGATEAREA 0.213000 ;
    PORT
      LAYER met3 ;
        RECT 763.425 265.240 767.425 265.840 ;
    END
  END x_in_flat[50]
  PIN x_in_flat[51]
    DIRECTION INPUT ;
    USE SIGNAL ;
    ANTENNAGATEAREA 0.247500 ;
    PORT
      LAYER met3 ;
        RECT 763.425 530.440 767.425 531.040 ;
    END
  END x_in_flat[51]
  PIN x_in_flat[52]
    DIRECTION INPUT ;
    USE SIGNAL ;
    ANTENNAGATEAREA 0.426000 ;
    PORT
      LAYER met2 ;
        RECT 248.030 0.000 248.310 4.000 ;
    END
  END x_in_flat[52]
  PIN x_in_flat[53]
    DIRECTION INPUT ;
    USE SIGNAL ;
    ANTENNAGATEAREA 0.426000 ;
    PORT
      LAYER met3 ;
        RECT 763.425 710.640 767.425 711.240 ;
    END
  END x_in_flat[53]
  PIN x_in_flat[54]
    DIRECTION INPUT ;
    USE SIGNAL ;
    ANTENNAGATEAREA 0.213000 ;
    PORT
      LAYER met3 ;
        RECT 763.425 170.040 767.425 170.640 ;
    END
  END x_in_flat[54]
  PIN x_in_flat[55]
    DIRECTION INPUT ;
    USE SIGNAL ;
    ANTENNAGATEAREA 0.426000 ;
    PORT
      LAYER met2 ;
        RECT 508.850 0.000 509.130 4.000 ;
    END
  END x_in_flat[55]
  PIN x_in_flat[56]
    DIRECTION INPUT ;
    USE SIGNAL ;
    ANTENNAGATEAREA 0.213000 ;
    PORT
      LAYER met3 ;
        RECT 763.425 734.440 767.425 735.040 ;
    END
  END x_in_flat[56]
  PIN x_in_flat[57]
    DIRECTION INPUT ;
    USE SIGNAL ;
    ANTENNAGATEAREA 0.742500 ;
    PORT
      LAYER met3 ;
        RECT 0.000 275.440 4.000 276.040 ;
    END
  END x_in_flat[57]
  PIN x_in_flat[58]
    DIRECTION INPUT ;
    USE SIGNAL ;
    ANTENNAGATEAREA 0.426000 ;
    PORT
      LAYER met2 ;
        RECT 202.950 0.000 203.230 4.000 ;
    END
  END x_in_flat[58]
  PIN x_in_flat[59]
    DIRECTION INPUT ;
    USE SIGNAL ;
    ANTENNAGATEAREA 0.742500 ;
    PORT
      LAYER met2 ;
        RECT 32.290 0.000 32.570 4.000 ;
    END
  END x_in_flat[59]
  PIN x_in_flat[5]
    DIRECTION INPUT ;
    USE SIGNAL ;
    ANTENNAGATEAREA 0.426000 ;
    PORT
      LAYER met2 ;
        RECT 656.970 0.000 657.250 4.000 ;
    END
  END x_in_flat[5]
  PIN x_in_flat[60]
    DIRECTION INPUT ;
    USE SIGNAL ;
    ANTENNAGATEAREA 0.159000 ;
    PORT
      LAYER met3 ;
        RECT 763.425 74.840 767.425 75.440 ;
    END
  END x_in_flat[60]
  PIN x_in_flat[61]
    DIRECTION INPUT ;
    USE SIGNAL ;
    ANTENNAGATEAREA 0.426000 ;
    PORT
      LAYER met2 ;
        RECT 489.530 774.145 489.810 778.145 ;
    END
  END x_in_flat[61]
  PIN x_in_flat[62]
    DIRECTION INPUT ;
    USE SIGNAL ;
    ANTENNAGATEAREA 0.213000 ;
    PORT
      LAYER met3 ;
        RECT 763.425 506.640 767.425 507.240 ;
    END
  END x_in_flat[62]
  PIN x_in_flat[63]
    DIRECTION INPUT ;
    USE SIGNAL ;
    ANTENNAGATEAREA 0.213000 ;
    PORT
      LAYER met2 ;
        RECT 112.790 774.145 113.070 778.145 ;
    END
  END x_in_flat[63]
  PIN x_in_flat[6]
    DIRECTION INPUT ;
    USE SIGNAL ;
    ANTENNAGATEAREA 0.742500 ;
    PORT
      LAYER met2 ;
        RECT 161.090 774.145 161.370 778.145 ;
    END
  END x_in_flat[6]
  PIN x_in_flat[7]
    DIRECTION INPUT ;
    USE SIGNAL ;
    ANTENNAGATEAREA 0.742500 ;
    PORT
      LAYER met2 ;
        RECT 135.330 774.145 135.610 778.145 ;
    END
  END x_in_flat[7]
  PIN x_in_flat[8]
    DIRECTION INPUT ;
    USE SIGNAL ;
    ANTENNAGATEAREA 0.742500 ;
    PORT
      LAYER met2 ;
        RECT 22.630 0.000 22.910 4.000 ;
    END
  END x_in_flat[8]
  PIN x_in_flat[9]
    DIRECTION INPUT ;
    USE SIGNAL ;
    ANTENNAGATEAREA 0.852000 ;
    PORT
      LAYER met3 ;
        RECT 0.000 261.840 4.000 262.440 ;
    END
  END x_in_flat[9]
  PIN y_out_flat[0]
    DIRECTION OUTPUT TRISTATE ;
    USE SIGNAL ;
    ANTENNADIFFAREA 0.445500 ;
    PORT
      LAYER met3 ;
        RECT 763.425 278.840 767.425 279.440 ;
    END
  END y_out_flat[0]
  PIN y_out_flat[10]
    DIRECTION OUTPUT TRISTATE ;
    USE SIGNAL ;
    ANTENNADIFFAREA 0.795200 ;
    PORT
      LAYER met2 ;
        RECT 386.490 0.000 386.770 4.000 ;
    END
  END y_out_flat[10]
  PIN y_out_flat[11]
    DIRECTION OUTPUT TRISTATE ;
    USE SIGNAL ;
    ANTENNADIFFAREA 0.795200 ;
    PORT
      LAYER met2 ;
        RECT 705.270 774.145 705.550 778.145 ;
    END
  END y_out_flat[11]
  PIN y_out_flat[12]
    DIRECTION OUTPUT TRISTATE ;
    USE SIGNAL ;
    ANTENNADIFFAREA 0.445500 ;
    PORT
      LAYER met3 ;
        RECT 763.425 673.240 767.425 673.840 ;
    END
  END y_out_flat[12]
  PIN y_out_flat[13]
    DIRECTION OUTPUT TRISTATE ;
    USE SIGNAL ;
    ANTENNADIFFAREA 0.795200 ;
    PORT
      LAYER met2 ;
        RECT 260.910 774.145 261.190 778.145 ;
    END
  END y_out_flat[13]
  PIN y_out_flat[14]
    DIRECTION OUTPUT TRISTATE ;
    USE SIGNAL ;
    ANTENNADIFFAREA 0.795200 ;
    PORT
      LAYER met2 ;
        RECT 99.910 0.000 100.190 4.000 ;
    END
  END y_out_flat[14]
  PIN y_out_flat[15]
    DIRECTION OUTPUT TRISTATE ;
    USE SIGNAL ;
    ANTENNADIFFAREA 0.795200 ;
    PORT
      LAYER met3 ;
        RECT 763.425 350.240 767.425 350.840 ;
    END
  END y_out_flat[15]
  PIN y_out_flat[16]
    DIRECTION OUTPUT TRISTATE ;
    USE SIGNAL ;
    ANTENNADIFFAREA 0.445500 ;
    PORT
      LAYER met3 ;
        RECT 763.425 663.040 767.425 663.640 ;
    END
  END y_out_flat[16]
  PIN y_out_flat[17]
    DIRECTION OUTPUT TRISTATE ;
    USE SIGNAL ;
    ANTENNADIFFAREA 0.795200 ;
    PORT
      LAYER met3 ;
        RECT 0.000 707.240 4.000 707.840 ;
    END
  END y_out_flat[17]
  PIN y_out_flat[18]
    DIRECTION OUTPUT TRISTATE ;
    USE SIGNAL ;
    ANTENNADIFFAREA 0.445500 ;
    PORT
      LAYER met3 ;
        RECT 763.425 482.840 767.425 483.440 ;
    END
  END y_out_flat[18]
  PIN y_out_flat[19]
    DIRECTION OUTPUT TRISTATE ;
    USE SIGNAL ;
    ANTENNADIFFAREA 0.445500 ;
    PORT
      LAYER met3 ;
        RECT 763.425 159.840 767.425 160.440 ;
    END
  END y_out_flat[19]
  PIN y_out_flat[1]
    DIRECTION OUTPUT TRISTATE ;
    USE SIGNAL ;
    ANTENNADIFFAREA 0.795200 ;
    PORT
      LAYER met2 ;
        RECT 476.650 0.000 476.930 4.000 ;
    END
  END y_out_flat[1]
  PIN y_out_flat[20]
    DIRECTION OUTPUT TRISTATE ;
    USE SIGNAL ;
    ANTENNADIFFAREA 0.795200 ;
    PORT
      LAYER met3 ;
        RECT 763.425 771.840 767.425 772.440 ;
    END
  END y_out_flat[20]
  PIN y_out_flat[21]
    DIRECTION OUTPUT TRISTATE ;
    USE SIGNAL ;
    ANTENNADIFFAREA 0.795200 ;
    PORT
      LAYER met2 ;
        RECT 363.950 774.145 364.230 778.145 ;
    END
  END y_out_flat[21]
  PIN y_out_flat[22]
    DIRECTION OUTPUT TRISTATE ;
    USE SIGNAL ;
    ANTENNADIFFAREA 0.795200 ;
    PORT
      LAYER met2 ;
        RECT 215.830 0.000 216.110 4.000 ;
    END
  END y_out_flat[22]
  PIN y_out_flat[23]
    DIRECTION OUTPUT TRISTATE ;
    USE SIGNAL ;
    ANTENNADIFFAREA 0.795200 ;
    PORT
      LAYER met3 ;
        RECT 0.000 442.040 4.000 442.640 ;
    END
  END y_out_flat[23]
  PIN y_out_flat[24]
    DIRECTION OUTPUT TRISTATE ;
    USE SIGNAL ;
    ANTENNADIFFAREA 0.795200 ;
    PORT
      LAYER met3 ;
        RECT 0.000 323.040 4.000 323.640 ;
    END
  END y_out_flat[24]
  PIN y_out_flat[25]
    DIRECTION OUTPUT TRISTATE ;
    USE SIGNAL ;
    ANTENNADIFFAREA 0.445500 ;
    PORT
      LAYER met3 ;
        RECT 763.425 146.240 767.425 146.840 ;
    END
  END y_out_flat[25]
  PIN y_out_flat[26]
    DIRECTION OUTPUT TRISTATE ;
    USE SIGNAL ;
    ANTENNADIFFAREA 0.795200 ;
    PORT
      LAYER met3 ;
        RECT 0.000 612.040 4.000 612.640 ;
    END
  END y_out_flat[26]
  PIN y_out_flat[27]
    DIRECTION OUTPUT TRISTATE ;
    USE SIGNAL ;
    ANTENNADIFFAREA 0.795200 ;
    PORT
      LAYER met2 ;
        RECT 727.810 0.000 728.090 4.000 ;
    END
  END y_out_flat[27]
  PIN y_out_flat[28]
    DIRECTION OUTPUT TRISTATE ;
    USE SIGNAL ;
    ANTENNADIFFAREA 0.795200 ;
    PORT
      LAYER met2 ;
        RECT 112.790 0.000 113.070 4.000 ;
    END
  END y_out_flat[28]
  PIN y_out_flat[29]
    DIRECTION OUTPUT TRISTATE ;
    USE SIGNAL ;
    ANTENNADIFFAREA 0.795200 ;
    PORT
      LAYER met2 ;
        RECT 351.070 0.000 351.350 4.000 ;
    END
  END y_out_flat[29]
  PIN y_out_flat[2]
    DIRECTION OUTPUT TRISTATE ;
    USE SIGNAL ;
    ANTENNADIFFAREA 0.445500 ;
    PORT
      LAYER met3 ;
        RECT 763.425 255.040 767.425 255.640 ;
    END
  END y_out_flat[2]
  PIN y_out_flat[30]
    DIRECTION OUTPUT TRISTATE ;
    USE SIGNAL ;
    ANTENNADIFFAREA 0.795200 ;
    PORT
      LAYER met2 ;
        RECT 718.150 774.145 718.430 778.145 ;
    END
  END y_out_flat[30]
  PIN y_out_flat[31]
    DIRECTION OUTPUT TRISTATE ;
    USE SIGNAL ;
    ANTENNADIFFAREA 0.445500 ;
    PORT
      LAYER met3 ;
        RECT 763.425 601.840 767.425 602.440 ;
    END
  END y_out_flat[31]
  PIN y_out_flat[32]
    DIRECTION OUTPUT TRISTATE ;
    USE SIGNAL ;
    ANTENNADIFFAREA 0.795200 ;
    PORT
      LAYER met2 ;
        RECT 750.350 0.000 750.630 4.000 ;
    END
  END y_out_flat[32]
  PIN y_out_flat[33]
    DIRECTION OUTPUT TRISTATE ;
    USE SIGNAL ;
    ANTENNADIFFAREA 0.795200 ;
    PORT
      LAYER met3 ;
        RECT 0.000 251.640 4.000 252.240 ;
    END
  END y_out_flat[33]
  PIN y_out_flat[34]
    DIRECTION OUTPUT TRISTATE ;
    USE SIGNAL ;
    ANTENNADIFFAREA 0.445500 ;
    PORT
      LAYER met3 ;
        RECT 763.425 363.840 767.425 364.440 ;
    END
  END y_out_flat[34]
  PIN y_out_flat[35]
    DIRECTION OUTPUT TRISTATE ;
    USE SIGNAL ;
    ANTENNADIFFAREA 0.795200 ;
    PORT
      LAYER met2 ;
        RECT 9.750 0.000 10.030 4.000 ;
    END
  END y_out_flat[35]
  PIN y_out_flat[36]
    DIRECTION OUTPUT TRISTATE ;
    USE SIGNAL ;
    ANTENNADIFFAREA 0.445500 ;
    PORT
      LAYER met3 ;
        RECT 763.425 639.240 767.425 639.840 ;
    END
  END y_out_flat[36]
  PIN y_out_flat[37]
    DIRECTION OUTPUT TRISTATE ;
    USE SIGNAL ;
    ANTENNADIFFAREA 0.795200 ;
    PORT
      LAYER met2 ;
        RECT 669.850 774.145 670.130 778.145 ;
    END
  END y_out_flat[37]
  PIN y_out_flat[38]
    DIRECTION OUTPUT TRISTATE ;
    USE SIGNAL ;
    ANTENNADIFFAREA 0.795200 ;
    PORT
      LAYER met3 ;
        RECT 763.425 27.240 767.425 27.840 ;
    END
  END y_out_flat[38]
  PIN y_out_flat[39]
    DIRECTION OUTPUT TRISTATE ;
    USE SIGNAL ;
    ANTENNADIFFAREA 0.795200 ;
    PORT
      LAYER met2 ;
        RECT 637.650 774.145 637.930 778.145 ;
    END
  END y_out_flat[39]
  PIN y_out_flat[3]
    DIRECTION OUTPUT TRISTATE ;
    USE SIGNAL ;
    ANTENNADIFFAREA 0.795200 ;
    PORT
      LAYER met3 ;
        RECT 0.000 346.840 4.000 347.440 ;
    END
  END y_out_flat[3]
  PIN y_out_flat[40]
    DIRECTION OUTPUT TRISTATE ;
    USE SIGNAL ;
    ANTENNADIFFAREA 0.795200 ;
    PORT
      LAYER met3 ;
        RECT 0.000 370.640 4.000 371.240 ;
    END
  END y_out_flat[40]
  PIN y_out_flat[41]
    DIRECTION OUTPUT TRISTATE ;
    USE SIGNAL ;
    ANTENNADIFFAREA 0.795200 ;
    PORT
      LAYER met2 ;
        RECT 486.310 0.000 486.590 4.000 ;
    END
  END y_out_flat[41]
  PIN y_out_flat[42]
    DIRECTION OUTPUT TRISTATE ;
    USE SIGNAL ;
    ANTENNADIFFAREA 0.795200 ;
    PORT
      LAYER met2 ;
        RECT 0.090 0.000 0.370 4.000 ;
    END
  END y_out_flat[42]
  PIN y_out_flat[43]
    DIRECTION OUTPUT TRISTATE ;
    USE SIGNAL ;
    ANTENNADIFFAREA 0.795200 ;
    PORT
      LAYER met2 ;
        RECT 566.810 0.000 567.090 4.000 ;
    END
  END y_out_flat[43]
  PIN y_out_flat[44]
    DIRECTION OUTPUT TRISTATE ;
    USE SIGNAL ;
    ANTENNADIFFAREA 0.795200 ;
    PORT
      LAYER met3 ;
        RECT 0.000 479.440 4.000 480.040 ;
    END
  END y_out_flat[44]
  PIN y_out_flat[45]
    DIRECTION OUTPUT TRISTATE ;
    USE SIGNAL ;
    ANTENNADIFFAREA 0.795200 ;
    PORT
      LAYER met2 ;
        RECT 0.090 774.145 0.370 778.145 ;
    END
  END y_out_flat[45]
  PIN y_out_flat[46]
    DIRECTION OUTPUT TRISTATE ;
    USE SIGNAL ;
    ANTENNADIFFAREA 0.795200 ;
    PORT
      LAYER met3 ;
        RECT 0.000 227.840 4.000 228.440 ;
    END
  END y_out_flat[46]
  PIN y_out_flat[47]
    DIRECTION OUTPUT TRISTATE ;
    USE SIGNAL ;
    ANTENNADIFFAREA 0.795200 ;
    PORT
      LAYER met3 ;
        RECT 0.000 357.040 4.000 357.640 ;
    END
  END y_out_flat[47]
  PIN y_out_flat[48]
    DIRECTION OUTPUT TRISTATE ;
    USE SIGNAL ;
    ANTENNADIFFAREA 0.795200 ;
    PORT
      LAYER met2 ;
        RECT 144.990 0.000 145.270 4.000 ;
    END
  END y_out_flat[48]
  PIN y_out_flat[49]
    DIRECTION OUTPUT TRISTATE ;
    USE SIGNAL ;
    ANTENNADIFFAREA 0.795200 ;
    PORT
      LAYER met2 ;
        RECT 54.830 0.000 55.110 4.000 ;
    END
  END y_out_flat[49]
  PIN y_out_flat[4]
    DIRECTION OUTPUT TRISTATE ;
    USE SIGNAL ;
    ANTENNADIFFAREA 0.795200 ;
    PORT
      LAYER met2 ;
        RECT 454.110 774.145 454.390 778.145 ;
    END
  END y_out_flat[4]
  PIN y_out_flat[50]
    DIRECTION OUTPUT TRISTATE ;
    USE SIGNAL ;
    ANTENNADIFFAREA 0.795200 ;
    PORT
      LAYER met2 ;
        RECT 296.330 774.145 296.610 778.145 ;
    END
  END y_out_flat[50]
  PIN y_out_flat[51]
    DIRECTION OUTPUT TRISTATE ;
    USE SIGNAL ;
    ANTENNADIFFAREA 0.795200 ;
    PORT
      LAYER met2 ;
        RECT 396.150 0.000 396.430 4.000 ;
    END
  END y_out_flat[51]
  PIN y_out_flat[52]
    DIRECTION OUTPUT TRISTATE ;
    USE SIGNAL ;
    ANTENNADIFFAREA 0.795200 ;
    PORT
      LAYER met2 ;
        RECT 579.690 774.145 579.970 778.145 ;
    END
  END y_out_flat[52]
  PIN y_out_flat[53]
    DIRECTION OUTPUT TRISTATE ;
    USE SIGNAL ;
    ANTENNADIFFAREA 0.445500 ;
    PORT
      LAYER met3 ;
        RECT 763.425 183.640 767.425 184.240 ;
    END
  END y_out_flat[53]
  PIN y_out_flat[54]
    DIRECTION OUTPUT TRISTATE ;
    USE SIGNAL ;
    ANTENNADIFFAREA 0.795200 ;
    PORT
      LAYER met3 ;
        RECT 0.000 574.640 4.000 575.240 ;
    END
  END y_out_flat[54]
  PIN y_out_flat[55]
    DIRECTION OUTPUT TRISTATE ;
    USE SIGNAL ;
    ANTENNADIFFAREA 0.445500 ;
    PORT
      LAYER met3 ;
        RECT 763.425 567.840 767.425 568.440 ;
    END
  END y_out_flat[55]
  PIN y_out_flat[56]
    DIRECTION OUTPUT TRISTATE ;
    USE SIGNAL ;
    ANTENNADIFFAREA 0.795200 ;
    PORT
      LAYER met2 ;
        RECT 157.870 0.000 158.150 4.000 ;
    END
  END y_out_flat[56]
  PIN y_out_flat[57]
    DIRECTION OUTPUT TRISTATE ;
    USE SIGNAL ;
    ANTENNADIFFAREA 0.795200 ;
    PORT
      LAYER met2 ;
        RECT 283.450 0.000 283.730 4.000 ;
    END
  END y_out_flat[57]
  PIN y_out_flat[58]
    DIRECTION OUTPUT TRISTATE ;
    USE SIGNAL ;
    ANTENNADIFFAREA 0.795200 ;
    PORT
      LAYER met2 ;
        RECT 441.230 0.000 441.510 4.000 ;
    END
  END y_out_flat[58]
  PIN y_out_flat[59]
    DIRECTION OUTPUT TRISTATE ;
    USE SIGNAL ;
    ANTENNADIFFAREA 0.445500 ;
    PORT
      LAYER met3 ;
        RECT 763.425 554.240 767.425 554.840 ;
    END
  END y_out_flat[59]
  PIN y_out_flat[5]
    DIRECTION OUTPUT TRISTATE ;
    USE SIGNAL ;
    ANTENNADIFFAREA 0.795200 ;
    PORT
      LAYER met2 ;
        RECT 454.110 0.000 454.390 4.000 ;
    END
  END y_out_flat[5]
  PIN y_out_flat[60]
    DIRECTION OUTPUT TRISTATE ;
    USE SIGNAL ;
    ANTENNADIFFAREA 0.795200 ;
    PORT
      LAYER met2 ;
        RECT 534.610 774.145 534.890 778.145 ;
    END
  END y_out_flat[60]
  PIN y_out_flat[61]
    DIRECTION OUTPUT TRISTATE ;
    USE SIGNAL ;
    ANTENNADIFFAREA 0.795200 ;
    PORT
      LAYER met2 ;
        RECT 512.070 774.145 512.350 778.145 ;
    END
  END y_out_flat[61]
  PIN y_out_flat[62]
    DIRECTION OUTPUT TRISTATE ;
    USE SIGNAL ;
    ANTENNADIFFAREA 0.795200 ;
    PORT
      LAYER met3 ;
        RECT 0.000 754.840 4.000 755.440 ;
    END
  END y_out_flat[62]
  PIN y_out_flat[63]
    DIRECTION OUTPUT TRISTATE ;
    USE SIGNAL ;
    ANTENNADIFFAREA 0.795200 ;
    PORT
      LAYER met2 ;
        RECT 103.130 774.145 103.410 778.145 ;
    END
  END y_out_flat[63]
  PIN y_out_flat[6]
    DIRECTION OUTPUT TRISTATE ;
    USE SIGNAL ;
    ANTENNADIFFAREA 0.795200 ;
    PORT
      LAYER met2 ;
        RECT 544.270 0.000 544.550 4.000 ;
    END
  END y_out_flat[6]
  PIN y_out_flat[7]
    DIRECTION OUTPUT TRISTATE ;
    USE SIGNAL ;
    ANTENNADIFFAREA 0.795200 ;
    PORT
      LAYER met3 ;
        RECT 0.000 176.840 4.000 177.440 ;
    END
  END y_out_flat[7]
  PIN y_out_flat[8]
    DIRECTION OUTPUT TRISTATE ;
    USE SIGNAL ;
    ANTENNADIFFAREA 0.795200 ;
    PORT
      LAYER met3 ;
        RECT 0.000 659.640 4.000 660.240 ;
    END
  END y_out_flat[8]
  PIN y_out_flat[9]
    DIRECTION OUTPUT TRISTATE ;
    USE SIGNAL ;
    ANTENNADIFFAREA 0.445500 ;
    PORT
      LAYER met3 ;
        RECT 763.425 374.040 767.425 374.640 ;
    END
  END y_out_flat[9]
  OBS
      LAYER li1 ;
        RECT 5.520 10.795 761.760 767.125 ;
      LAYER met1 ;
        RECT 0.070 8.200 764.910 768.700 ;
      LAYER met2 ;
        RECT 0.650 773.865 12.690 774.930 ;
        RECT 13.530 773.865 22.350 774.930 ;
        RECT 23.190 773.865 35.230 774.930 ;
        RECT 36.070 773.865 44.890 774.930 ;
        RECT 45.730 773.865 57.770 774.930 ;
        RECT 58.610 773.865 67.430 774.930 ;
        RECT 68.270 773.865 80.310 774.930 ;
        RECT 81.150 773.865 89.970 774.930 ;
        RECT 90.810 773.865 102.850 774.930 ;
        RECT 103.690 773.865 112.510 774.930 ;
        RECT 113.350 773.865 125.390 774.930 ;
        RECT 126.230 773.865 135.050 774.930 ;
        RECT 135.890 773.865 147.930 774.930 ;
        RECT 148.770 773.865 160.810 774.930 ;
        RECT 161.650 773.865 170.470 774.930 ;
        RECT 171.310 773.865 183.350 774.930 ;
        RECT 184.190 773.865 193.010 774.930 ;
        RECT 193.850 773.865 205.890 774.930 ;
        RECT 206.730 773.865 215.550 774.930 ;
        RECT 216.390 773.865 228.430 774.930 ;
        RECT 229.270 773.865 238.090 774.930 ;
        RECT 238.930 773.865 250.970 774.930 ;
        RECT 251.810 773.865 260.630 774.930 ;
        RECT 261.470 773.865 273.510 774.930 ;
        RECT 274.350 773.865 283.170 774.930 ;
        RECT 284.010 773.865 296.050 774.930 ;
        RECT 296.890 773.865 305.710 774.930 ;
        RECT 306.550 773.865 318.590 774.930 ;
        RECT 319.430 773.865 331.470 774.930 ;
        RECT 332.310 773.865 341.130 774.930 ;
        RECT 341.970 773.865 354.010 774.930 ;
        RECT 354.850 773.865 363.670 774.930 ;
        RECT 364.510 773.865 376.550 774.930 ;
        RECT 377.390 773.865 386.210 774.930 ;
        RECT 387.050 773.865 399.090 774.930 ;
        RECT 399.930 773.865 408.750 774.930 ;
        RECT 409.590 773.865 421.630 774.930 ;
        RECT 422.470 773.865 431.290 774.930 ;
        RECT 432.130 773.865 444.170 774.930 ;
        RECT 445.010 773.865 453.830 774.930 ;
        RECT 454.670 773.865 466.710 774.930 ;
        RECT 467.550 773.865 476.370 774.930 ;
        RECT 477.210 773.865 489.250 774.930 ;
        RECT 490.090 773.865 498.910 774.930 ;
        RECT 499.750 773.865 511.790 774.930 ;
        RECT 512.630 773.865 524.670 774.930 ;
        RECT 525.510 773.865 534.330 774.930 ;
        RECT 535.170 773.865 547.210 774.930 ;
        RECT 548.050 773.865 556.870 774.930 ;
        RECT 557.710 773.865 569.750 774.930 ;
        RECT 570.590 773.865 579.410 774.930 ;
        RECT 580.250 773.865 592.290 774.930 ;
        RECT 593.130 773.865 601.950 774.930 ;
        RECT 602.790 773.865 614.830 774.930 ;
        RECT 615.670 773.865 624.490 774.930 ;
        RECT 625.330 773.865 637.370 774.930 ;
        RECT 638.210 773.865 647.030 774.930 ;
        RECT 647.870 773.865 659.910 774.930 ;
        RECT 660.750 773.865 669.570 774.930 ;
        RECT 670.410 773.865 682.450 774.930 ;
        RECT 683.290 773.865 695.330 774.930 ;
        RECT 696.170 773.865 704.990 774.930 ;
        RECT 705.830 773.865 717.870 774.930 ;
        RECT 718.710 773.865 727.530 774.930 ;
        RECT 728.370 773.865 740.410 774.930 ;
        RECT 741.250 773.865 750.070 774.930 ;
        RECT 750.910 773.865 762.950 774.930 ;
        RECT 763.790 773.865 764.880 774.930 ;
        RECT 0.100 4.280 764.880 773.865 ;
        RECT 0.650 3.670 9.470 4.280 ;
        RECT 10.310 3.670 22.350 4.280 ;
        RECT 23.190 3.670 32.010 4.280 ;
        RECT 32.850 3.670 44.890 4.280 ;
        RECT 45.730 3.670 54.550 4.280 ;
        RECT 55.390 3.670 67.430 4.280 ;
        RECT 68.270 3.670 77.090 4.280 ;
        RECT 77.930 3.670 89.970 4.280 ;
        RECT 90.810 3.670 99.630 4.280 ;
        RECT 100.470 3.670 112.510 4.280 ;
        RECT 113.350 3.670 122.170 4.280 ;
        RECT 123.010 3.670 135.050 4.280 ;
        RECT 135.890 3.670 144.710 4.280 ;
        RECT 145.550 3.670 157.590 4.280 ;
        RECT 158.430 3.670 167.250 4.280 ;
        RECT 168.090 3.670 180.130 4.280 ;
        RECT 180.970 3.670 193.010 4.280 ;
        RECT 193.850 3.670 202.670 4.280 ;
        RECT 203.510 3.670 215.550 4.280 ;
        RECT 216.390 3.670 225.210 4.280 ;
        RECT 226.050 3.670 238.090 4.280 ;
        RECT 238.930 3.670 247.750 4.280 ;
        RECT 248.590 3.670 260.630 4.280 ;
        RECT 261.470 3.670 270.290 4.280 ;
        RECT 271.130 3.670 283.170 4.280 ;
        RECT 284.010 3.670 292.830 4.280 ;
        RECT 293.670 3.670 305.710 4.280 ;
        RECT 306.550 3.670 315.370 4.280 ;
        RECT 316.210 3.670 328.250 4.280 ;
        RECT 329.090 3.670 337.910 4.280 ;
        RECT 338.750 3.670 350.790 4.280 ;
        RECT 351.630 3.670 363.670 4.280 ;
        RECT 364.510 3.670 373.330 4.280 ;
        RECT 374.170 3.670 386.210 4.280 ;
        RECT 387.050 3.670 395.870 4.280 ;
        RECT 396.710 3.670 408.750 4.280 ;
        RECT 409.590 3.670 418.410 4.280 ;
        RECT 419.250 3.670 431.290 4.280 ;
        RECT 432.130 3.670 440.950 4.280 ;
        RECT 441.790 3.670 453.830 4.280 ;
        RECT 454.670 3.670 463.490 4.280 ;
        RECT 464.330 3.670 476.370 4.280 ;
        RECT 477.210 3.670 486.030 4.280 ;
        RECT 486.870 3.670 498.910 4.280 ;
        RECT 499.750 3.670 508.570 4.280 ;
        RECT 509.410 3.670 521.450 4.280 ;
        RECT 522.290 3.670 534.330 4.280 ;
        RECT 535.170 3.670 543.990 4.280 ;
        RECT 544.830 3.670 556.870 4.280 ;
        RECT 557.710 3.670 566.530 4.280 ;
        RECT 567.370 3.670 579.410 4.280 ;
        RECT 580.250 3.670 589.070 4.280 ;
        RECT 589.910 3.670 601.950 4.280 ;
        RECT 602.790 3.670 611.610 4.280 ;
        RECT 612.450 3.670 624.490 4.280 ;
        RECT 625.330 3.670 634.150 4.280 ;
        RECT 634.990 3.670 647.030 4.280 ;
        RECT 647.870 3.670 656.690 4.280 ;
        RECT 657.530 3.670 669.570 4.280 ;
        RECT 670.410 3.670 679.230 4.280 ;
        RECT 680.070 3.670 692.110 4.280 ;
        RECT 692.950 3.670 701.770 4.280 ;
        RECT 702.610 3.670 714.650 4.280 ;
        RECT 715.490 3.670 727.530 4.280 ;
        RECT 728.370 3.670 737.190 4.280 ;
        RECT 738.030 3.670 750.070 4.280 ;
        RECT 750.910 3.670 759.730 4.280 ;
        RECT 760.570 3.670 764.880 4.280 ;
      LAYER met3 ;
        RECT 3.990 771.440 763.025 772.305 ;
        RECT 3.990 769.440 763.425 771.440 ;
        RECT 4.400 768.040 763.425 769.440 ;
        RECT 3.990 759.240 763.425 768.040 ;
        RECT 3.990 757.840 763.025 759.240 ;
        RECT 3.990 755.840 763.425 757.840 ;
        RECT 4.400 754.440 763.425 755.840 ;
        RECT 3.990 749.040 763.425 754.440 ;
        RECT 3.990 747.640 763.025 749.040 ;
        RECT 3.990 742.240 763.425 747.640 ;
        RECT 4.400 740.840 763.425 742.240 ;
        RECT 3.990 735.440 763.425 740.840 ;
        RECT 3.990 734.040 763.025 735.440 ;
        RECT 3.990 732.040 763.425 734.040 ;
        RECT 4.400 730.640 763.425 732.040 ;
        RECT 3.990 725.240 763.425 730.640 ;
        RECT 3.990 723.840 763.025 725.240 ;
        RECT 3.990 718.440 763.425 723.840 ;
        RECT 4.400 717.040 763.425 718.440 ;
        RECT 3.990 711.640 763.425 717.040 ;
        RECT 3.990 710.240 763.025 711.640 ;
        RECT 3.990 708.240 763.425 710.240 ;
        RECT 4.400 706.840 763.425 708.240 ;
        RECT 3.990 701.440 763.425 706.840 ;
        RECT 3.990 700.040 763.025 701.440 ;
        RECT 3.990 694.640 763.425 700.040 ;
        RECT 4.400 693.240 763.425 694.640 ;
        RECT 3.990 687.840 763.425 693.240 ;
        RECT 3.990 686.440 763.025 687.840 ;
        RECT 3.990 684.440 763.425 686.440 ;
        RECT 4.400 683.040 763.425 684.440 ;
        RECT 3.990 674.240 763.425 683.040 ;
        RECT 3.990 672.840 763.025 674.240 ;
        RECT 3.990 670.840 763.425 672.840 ;
        RECT 4.400 669.440 763.425 670.840 ;
        RECT 3.990 664.040 763.425 669.440 ;
        RECT 3.990 662.640 763.025 664.040 ;
        RECT 3.990 660.640 763.425 662.640 ;
        RECT 4.400 659.240 763.425 660.640 ;
        RECT 3.990 650.440 763.425 659.240 ;
        RECT 3.990 649.040 763.025 650.440 ;
        RECT 3.990 647.040 763.425 649.040 ;
        RECT 4.400 645.640 763.425 647.040 ;
        RECT 3.990 640.240 763.425 645.640 ;
        RECT 3.990 638.840 763.025 640.240 ;
        RECT 3.990 636.840 763.425 638.840 ;
        RECT 4.400 635.440 763.425 636.840 ;
        RECT 3.990 626.640 763.425 635.440 ;
        RECT 3.990 625.240 763.025 626.640 ;
        RECT 3.990 623.240 763.425 625.240 ;
        RECT 4.400 621.840 763.425 623.240 ;
        RECT 3.990 616.440 763.425 621.840 ;
        RECT 3.990 615.040 763.025 616.440 ;
        RECT 3.990 613.040 763.425 615.040 ;
        RECT 4.400 611.640 763.425 613.040 ;
        RECT 3.990 602.840 763.425 611.640 ;
        RECT 3.990 601.440 763.025 602.840 ;
        RECT 3.990 599.440 763.425 601.440 ;
        RECT 4.400 598.040 763.425 599.440 ;
        RECT 3.990 592.640 763.425 598.040 ;
        RECT 3.990 591.240 763.025 592.640 ;
        RECT 3.990 589.240 763.425 591.240 ;
        RECT 4.400 587.840 763.425 589.240 ;
        RECT 3.990 579.040 763.425 587.840 ;
        RECT 3.990 577.640 763.025 579.040 ;
        RECT 3.990 575.640 763.425 577.640 ;
        RECT 4.400 574.240 763.425 575.640 ;
        RECT 3.990 568.840 763.425 574.240 ;
        RECT 3.990 567.440 763.025 568.840 ;
        RECT 3.990 565.440 763.425 567.440 ;
        RECT 4.400 564.040 763.425 565.440 ;
        RECT 3.990 555.240 763.425 564.040 ;
        RECT 3.990 553.840 763.025 555.240 ;
        RECT 3.990 551.840 763.425 553.840 ;
        RECT 4.400 550.440 763.425 551.840 ;
        RECT 3.990 545.040 763.425 550.440 ;
        RECT 3.990 543.640 763.025 545.040 ;
        RECT 3.990 538.240 763.425 543.640 ;
        RECT 4.400 536.840 763.425 538.240 ;
        RECT 3.990 531.440 763.425 536.840 ;
        RECT 3.990 530.040 763.025 531.440 ;
        RECT 3.990 528.040 763.425 530.040 ;
        RECT 4.400 526.640 763.425 528.040 ;
        RECT 3.990 521.240 763.425 526.640 ;
        RECT 3.990 519.840 763.025 521.240 ;
        RECT 3.990 514.440 763.425 519.840 ;
        RECT 4.400 513.040 763.425 514.440 ;
        RECT 3.990 507.640 763.425 513.040 ;
        RECT 3.990 506.240 763.025 507.640 ;
        RECT 3.990 504.240 763.425 506.240 ;
        RECT 4.400 502.840 763.425 504.240 ;
        RECT 3.990 494.040 763.425 502.840 ;
        RECT 3.990 492.640 763.025 494.040 ;
        RECT 3.990 490.640 763.425 492.640 ;
        RECT 4.400 489.240 763.425 490.640 ;
        RECT 3.990 483.840 763.425 489.240 ;
        RECT 3.990 482.440 763.025 483.840 ;
        RECT 3.990 480.440 763.425 482.440 ;
        RECT 4.400 479.040 763.425 480.440 ;
        RECT 3.990 470.240 763.425 479.040 ;
        RECT 3.990 468.840 763.025 470.240 ;
        RECT 3.990 466.840 763.425 468.840 ;
        RECT 4.400 465.440 763.425 466.840 ;
        RECT 3.990 460.040 763.425 465.440 ;
        RECT 3.990 458.640 763.025 460.040 ;
        RECT 3.990 456.640 763.425 458.640 ;
        RECT 4.400 455.240 763.425 456.640 ;
        RECT 3.990 446.440 763.425 455.240 ;
        RECT 3.990 445.040 763.025 446.440 ;
        RECT 3.990 443.040 763.425 445.040 ;
        RECT 4.400 441.640 763.425 443.040 ;
        RECT 3.990 436.240 763.425 441.640 ;
        RECT 3.990 434.840 763.025 436.240 ;
        RECT 3.990 432.840 763.425 434.840 ;
        RECT 4.400 431.440 763.425 432.840 ;
        RECT 3.990 422.640 763.425 431.440 ;
        RECT 3.990 421.240 763.025 422.640 ;
        RECT 3.990 419.240 763.425 421.240 ;
        RECT 4.400 417.840 763.425 419.240 ;
        RECT 3.990 412.440 763.425 417.840 ;
        RECT 3.990 411.040 763.025 412.440 ;
        RECT 3.990 409.040 763.425 411.040 ;
        RECT 4.400 407.640 763.425 409.040 ;
        RECT 3.990 398.840 763.425 407.640 ;
        RECT 3.990 397.440 763.025 398.840 ;
        RECT 3.990 395.440 763.425 397.440 ;
        RECT 4.400 394.040 763.425 395.440 ;
        RECT 3.990 388.640 763.425 394.040 ;
        RECT 3.990 387.240 763.025 388.640 ;
        RECT 3.990 385.240 763.425 387.240 ;
        RECT 4.400 383.840 763.425 385.240 ;
        RECT 3.990 375.040 763.425 383.840 ;
        RECT 3.990 373.640 763.025 375.040 ;
        RECT 3.990 371.640 763.425 373.640 ;
        RECT 4.400 370.240 763.425 371.640 ;
        RECT 3.990 364.840 763.425 370.240 ;
        RECT 3.990 363.440 763.025 364.840 ;
        RECT 3.990 358.040 763.425 363.440 ;
        RECT 4.400 356.640 763.425 358.040 ;
        RECT 3.990 351.240 763.425 356.640 ;
        RECT 3.990 349.840 763.025 351.240 ;
        RECT 3.990 347.840 763.425 349.840 ;
        RECT 4.400 346.440 763.425 347.840 ;
        RECT 3.990 341.040 763.425 346.440 ;
        RECT 3.990 339.640 763.025 341.040 ;
        RECT 3.990 334.240 763.425 339.640 ;
        RECT 4.400 332.840 763.425 334.240 ;
        RECT 3.990 327.440 763.425 332.840 ;
        RECT 3.990 326.040 763.025 327.440 ;
        RECT 3.990 324.040 763.425 326.040 ;
        RECT 4.400 322.640 763.425 324.040 ;
        RECT 3.990 317.240 763.425 322.640 ;
        RECT 3.990 315.840 763.025 317.240 ;
        RECT 3.990 310.440 763.425 315.840 ;
        RECT 4.400 309.040 763.425 310.440 ;
        RECT 3.990 303.640 763.425 309.040 ;
        RECT 3.990 302.240 763.025 303.640 ;
        RECT 3.990 300.240 763.425 302.240 ;
        RECT 4.400 298.840 763.425 300.240 ;
        RECT 3.990 290.040 763.425 298.840 ;
        RECT 3.990 288.640 763.025 290.040 ;
        RECT 3.990 286.640 763.425 288.640 ;
        RECT 4.400 285.240 763.425 286.640 ;
        RECT 3.990 279.840 763.425 285.240 ;
        RECT 3.990 278.440 763.025 279.840 ;
        RECT 3.990 276.440 763.425 278.440 ;
        RECT 4.400 275.040 763.425 276.440 ;
        RECT 3.990 266.240 763.425 275.040 ;
        RECT 3.990 264.840 763.025 266.240 ;
        RECT 3.990 262.840 763.425 264.840 ;
        RECT 4.400 261.440 763.425 262.840 ;
        RECT 3.990 256.040 763.425 261.440 ;
        RECT 3.990 254.640 763.025 256.040 ;
        RECT 3.990 252.640 763.425 254.640 ;
        RECT 4.400 251.240 763.425 252.640 ;
        RECT 3.990 242.440 763.425 251.240 ;
        RECT 3.990 241.040 763.025 242.440 ;
        RECT 3.990 239.040 763.425 241.040 ;
        RECT 4.400 237.640 763.425 239.040 ;
        RECT 3.990 232.240 763.425 237.640 ;
        RECT 3.990 230.840 763.025 232.240 ;
        RECT 3.990 228.840 763.425 230.840 ;
        RECT 4.400 227.440 763.425 228.840 ;
        RECT 3.990 218.640 763.425 227.440 ;
        RECT 3.990 217.240 763.025 218.640 ;
        RECT 3.990 215.240 763.425 217.240 ;
        RECT 4.400 213.840 763.425 215.240 ;
        RECT 3.990 208.440 763.425 213.840 ;
        RECT 3.990 207.040 763.025 208.440 ;
        RECT 3.990 205.040 763.425 207.040 ;
        RECT 4.400 203.640 763.425 205.040 ;
        RECT 3.990 194.840 763.425 203.640 ;
        RECT 3.990 193.440 763.025 194.840 ;
        RECT 3.990 191.440 763.425 193.440 ;
        RECT 4.400 190.040 763.425 191.440 ;
        RECT 3.990 184.640 763.425 190.040 ;
        RECT 3.990 183.240 763.025 184.640 ;
        RECT 3.990 177.840 763.425 183.240 ;
        RECT 4.400 176.440 763.425 177.840 ;
        RECT 3.990 171.040 763.425 176.440 ;
        RECT 3.990 169.640 763.025 171.040 ;
        RECT 3.990 167.640 763.425 169.640 ;
        RECT 4.400 166.240 763.425 167.640 ;
        RECT 3.990 160.840 763.425 166.240 ;
        RECT 3.990 159.440 763.025 160.840 ;
        RECT 3.990 154.040 763.425 159.440 ;
        RECT 4.400 152.640 763.425 154.040 ;
        RECT 3.990 147.240 763.425 152.640 ;
        RECT 3.990 145.840 763.025 147.240 ;
        RECT 3.990 143.840 763.425 145.840 ;
        RECT 4.400 142.440 763.425 143.840 ;
        RECT 3.990 137.040 763.425 142.440 ;
        RECT 3.990 135.640 763.025 137.040 ;
        RECT 3.990 130.240 763.425 135.640 ;
        RECT 4.400 128.840 763.425 130.240 ;
        RECT 3.990 123.440 763.425 128.840 ;
        RECT 3.990 122.040 763.025 123.440 ;
        RECT 3.990 120.040 763.425 122.040 ;
        RECT 4.400 118.640 763.425 120.040 ;
        RECT 3.990 109.840 763.425 118.640 ;
        RECT 3.990 108.440 763.025 109.840 ;
        RECT 3.990 106.440 763.425 108.440 ;
        RECT 4.400 105.040 763.425 106.440 ;
        RECT 3.990 99.640 763.425 105.040 ;
        RECT 3.990 98.240 763.025 99.640 ;
        RECT 3.990 96.240 763.425 98.240 ;
        RECT 4.400 94.840 763.425 96.240 ;
        RECT 3.990 86.040 763.425 94.840 ;
        RECT 3.990 84.640 763.025 86.040 ;
        RECT 3.990 82.640 763.425 84.640 ;
        RECT 4.400 81.240 763.425 82.640 ;
        RECT 3.990 75.840 763.425 81.240 ;
        RECT 3.990 74.440 763.025 75.840 ;
        RECT 3.990 72.440 763.425 74.440 ;
        RECT 4.400 71.040 763.425 72.440 ;
        RECT 3.990 62.240 763.425 71.040 ;
        RECT 3.990 60.840 763.025 62.240 ;
        RECT 3.990 58.840 763.425 60.840 ;
        RECT 4.400 57.440 763.425 58.840 ;
        RECT 3.990 52.040 763.425 57.440 ;
        RECT 3.990 50.640 763.025 52.040 ;
        RECT 3.990 48.640 763.425 50.640 ;
        RECT 4.400 47.240 763.425 48.640 ;
        RECT 3.990 38.440 763.425 47.240 ;
        RECT 3.990 37.040 763.025 38.440 ;
        RECT 3.990 35.040 763.425 37.040 ;
        RECT 4.400 33.640 763.425 35.040 ;
        RECT 3.990 28.240 763.425 33.640 ;
        RECT 3.990 26.840 763.025 28.240 ;
        RECT 3.990 24.840 763.425 26.840 ;
        RECT 4.400 23.440 763.425 24.840 ;
        RECT 3.990 14.640 763.425 23.440 ;
        RECT 3.990 13.240 763.025 14.640 ;
        RECT 3.990 11.240 763.425 13.240 ;
        RECT 4.400 9.840 763.425 11.240 ;
        RECT 3.990 4.440 763.425 9.840 ;
        RECT 3.990 3.590 763.025 4.440 ;
      LAYER met4 ;
        RECT 14.095 9.695 20.640 762.785 ;
        RECT 23.040 9.695 23.940 762.785 ;
        RECT 26.340 9.695 174.240 762.785 ;
        RECT 176.640 9.695 177.540 762.785 ;
        RECT 179.940 9.695 327.840 762.785 ;
        RECT 330.240 9.695 331.140 762.785 ;
        RECT 333.540 9.695 481.440 762.785 ;
        RECT 483.840 9.695 484.740 762.785 ;
        RECT 487.140 9.695 635.040 762.785 ;
        RECT 637.440 9.695 638.340 762.785 ;
        RECT 640.740 9.695 751.345 762.785 ;
  END
END compute_core
END LIBRARY

